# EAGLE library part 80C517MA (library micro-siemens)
MICROPROCESSOR/PERIPHERAL DEVICE

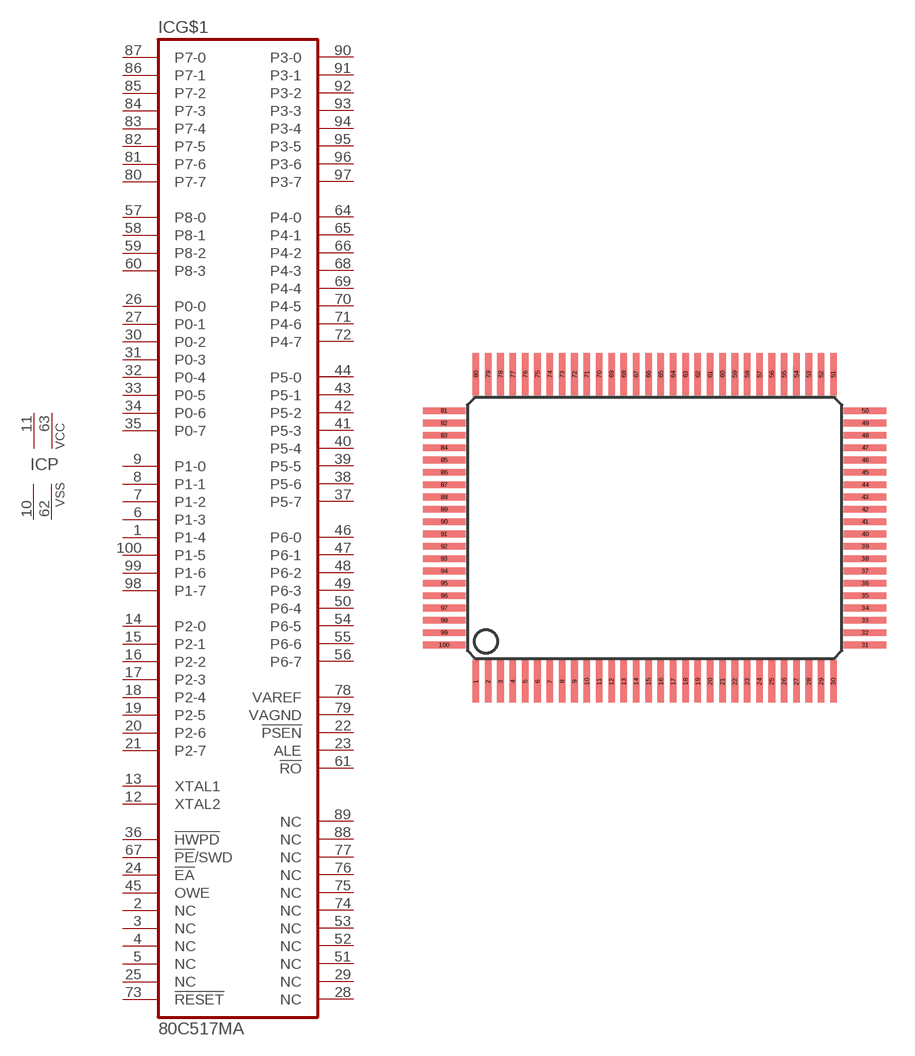
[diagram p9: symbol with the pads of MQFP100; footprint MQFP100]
Designator prefix IC; gates G$1=80C517MA P=2VCC2VSS

## 80C517MA (OC_FARNELL: unknown; OC_NEWARK: unknown)  [MQFP100]
1  G$1:P1-4
2  G$1:NC  nc
3  G$1:NC  nc
4  G$1:NC  nc
5  G$1:NC  nc
6  G$1:P1-3
7  G$1:P1-2
8  G$1:P1-1
9  G$1:P1-0
10  P:VSS  pwr
11  P:VCC  pwr
12  G$1:XTAL2  pas
13  G$1:XTAL1  pas
14  G$1:P2-0
15  G$1:P2-1
16  G$1:P2-2
17  G$1:P2-3
18  G$1:P2-4
19  G$1:P2-5
20  G$1:P2-6
21  G$1:P2-7
22  G$1:!PSEN  out
23  G$1:ALE  out
24  G$1:!EA  in
25  G$1:NC  nc
26  G$1:P0-0
27  G$1:P0-1
28  G$1:NC  nc
29  G$1:NC  nc
30  G$1:P0-2
31  G$1:P0-3
32  G$1:P0-4
33  G$1:P0-5
34  G$1:P0-6
35  G$1:P0-7
36  G$1:!HWPD  in
37  G$1:P5-7
38  G$1:P5-6
39  G$1:P5-5
40  G$1:P5-4
41  G$1:P5-3
42  G$1:P5-2
43  G$1:P5-1
44  G$1:P5-0
45  G$1:OWE  in
46  G$1:P6-0
47  G$1:P6-1
48  G$1:P6-2
49  G$1:P6-3
50  G$1:P6-4
51  G$1:NC  nc
52  G$1:NC  nc
53  G$1:NC  nc
54  G$1:P6-5
55  G$1:P6-6
56  G$1:P6-7
57  G$1:P8-0  in
58  G$1:P8-1  in
59  G$1:P8-2  in
60  G$1:P8-3  in
61  G$1:!RO  out
62  P:VSS  pwr
63  P:VCC  pwr
64  G$1:P4-0
65  G$1:P4-1
66  G$1:P4-2
67  G$1:!PE!/SWD  in
68  G$1:P4-3
69  G$1:P4-4
70  G$1:P4-5
71  G$1:P4-6
72  G$1:P4-7
73  G$1:!RESET  in
74  G$1:NC  nc
75  G$1:NC  nc
76  G$1:NC  nc
77  G$1:NC  nc
78  G$1:VAREF  pas
79  G$1:VAGND  pas
80  G$1:P7-7  in
81  G$1:P7-6  in
82  G$1:P7-5  in
83  G$1:P7-4  in
84  G$1:P7-3  in
85  G$1:P7-2  in
86  G$1:P7-1  in
87  G$1:P7-0  in
88  G$1:NC  nc
89  G$1:NC  nc
90  G$1:P3-0
91  G$1:P3-1
92  G$1:P3-2
93  G$1:P3-3
94  G$1:P3-4
95  G$1:P3-5
96  G$1:P3-6
97  G$1:P3-7
98  G$1:P1-7
99  G$1:P1-6
100  G$1:P1-5

## Footprint MQFP100 (pad centres in mm)
Metric Quad Flat Pack
smd 0.35 x 2.2: 1 -9.425,-8.1; 2 -8.775,-8.1; 3 -8.125,-8.1; 4 -7.475,-8.1; 5 -6.825,-8.1; 6 -6.175,-8.1; 7 -5.525,-8.1; 8 -4.875,-8.1; 9 -4.225,-8.1; 10 -3.575,-8.1; 11 -2.925,-8.1; 12 -2.275,-8.1; 13 -1.625,-8.1; 14 -0.975,-8.1; 15 -0.325,-8.1; 16 0.325,-8.1; 17 0.975,-8.1; 18 1.625,-8.1; 19 2.275,-8.1; 20 2.925,-8.1; 21 3.575,-8.1; 22 4.225,-8.1; 23 4.875,-8.1; 24 5.525,-8.1; 25 6.175,-8.1; 26 6.825,-8.1; 27 7.475,-8.1; 28 8.125,-8.1; 29 8.775,-8.1; 30 9.425,-8.1; 51 9.425,8.1; 52 8.775,8.1; 53 8.125,8.1; 54 7.475,8.1; 55 6.825,8.1; 56 6.175,8.1; 57 5.525,8.1; 58 4.875,8.1; 59 4.225,8.1; 60 3.575,8.1; 61 2.925,8.1; 62 2.275,8.1; 63 1.625,8.1; 64 0.975,8.1; 65 0.325,8.1; 66 -0.325,8.1; 67 -0.975,8.1; 68 -1.625,8.1; 69 -2.275,8.1; 70 -2.925,8.1; 71 -3.575,8.1; 72 -4.225,8.1; 73 -4.875,8.1; 74 -5.525,8.1; 75 -6.175,8.1; 76 -6.825,8.1; 77 -7.475,8.1; 78 -8.125,8.1; 79 -8.775,8.1; 80 -9.425,8.1
smd 2.2 x 0.35: 31 11.1,-6.175; 32 11.1,-5.525; 33 11.1,-4.875; 34 11.1,-4.225; 35 11.1,-3.575; 36 11.1,-2.925; 37 11.1,-2.275; 38 11.1,-1.625; 39 11.1,-0.975; 40 11.1,-0.325; 41 11.1,0.325; 42 11.1,0.975; 43 11.1,1.625; 44 11.1,2.275; 45 11.1,2.925; 46 11.1,3.575; 47 11.1,4.225; 48 11.1,4.875; 49 11.1,5.525; 50 11.1,6.175; 81 -11.1,6.175; 82 -11.1,5.525; 83 -11.1,4.875; 84 -11.1,4.225; 85 -11.1,3.575; 86 -11.1,2.925; 87 -11.1,2.275; 88 -11.1,1.625; 89 -11.1,0.975; 90 -11.1,0.325; 91 -11.1,-0.325; 92 -11.1,-0.975; 93 -11.1,-1.625; 94 -11.1,-2.275; 95 -11.1,-2.925; 96 -11.1,-3.575; 97 -11.1,-4.225; 98 -11.1,-4.875; 99 -11.1,-5.525; 100 -11.1,-6.175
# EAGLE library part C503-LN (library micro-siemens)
MICROPROCESSOR/PERIPHERAL DEVICE

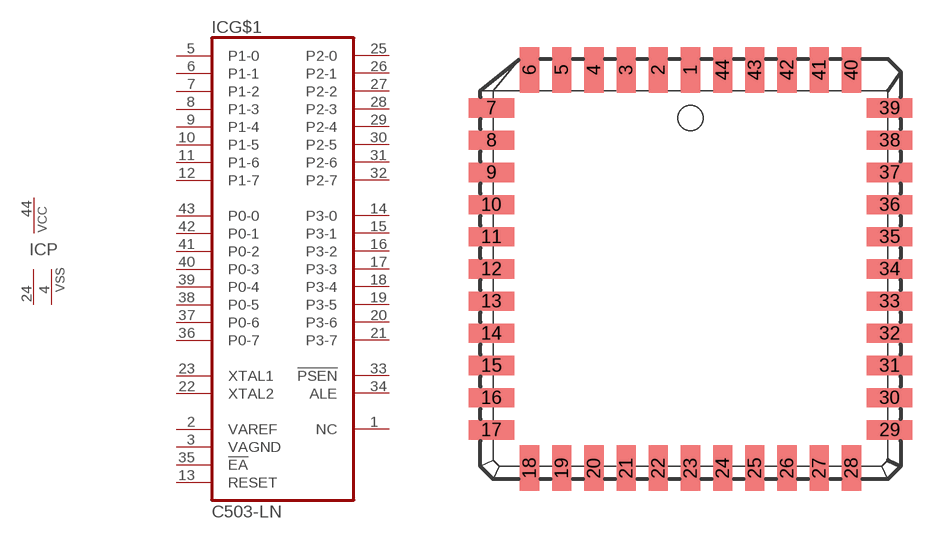
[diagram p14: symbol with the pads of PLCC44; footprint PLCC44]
Designator prefix IC; gates G$1=C503-LN P=1VCC2VSS

## C503-LN (OC_FARNELL: unknown; OC_NEWARK: unknown)  [PLCC44]
1  G$1:NC  nc
2  G$1:VAREF  pas
3  G$1:VAGND  pas
4  P:VSS  pwr
5  G$1:P1-0  in
6  G$1:P1-1  in
7  G$1:P1-2  in
8  G$1:P1-3  in
9  G$1:P1-4  in
10  G$1:P1-5  in
11  G$1:P1-6  in
12  G$1:P1-7  in
13  G$1:RESET  in
14  G$1:P3-0
15  G$1:P3-1
16  G$1:P3-2
17  G$1:P3-3
18  G$1:P3-4
19  G$1:P3-5
20  G$1:P3-6
21  G$1:P3-7
22  G$1:XTAL2  pas
23  G$1:XTAL1  pas
24  P:VSS  pwr
25  G$1:P2-0
26  G$1:P2-1
27  G$1:P2-2
28  G$1:P2-3
29  G$1:P2-4
30  G$1:P2-5
31  G$1:P2-6
32  G$1:P2-7
33  G$1:!PSEN  out
34  G$1:ALE  out
35  G$1:!EA  in
36  G$1:P0-7
37  G$1:P0-6
38  G$1:P0-5
39  G$1:P0-4
40  G$1:P0-3
41  G$1:P0-2
42  G$1:P0-1
43  G$1:P0-0
44  P:VCC  pwr

## Footprint PLCC44 (pad centres in mm)
PLASTIC LEADED CHIP CARRIER square
smd 0.76 x 1.8: 1 0,7.86; 2 -1.27,7.86; 3 -2.54,7.86; 4 -3.81,7.86; 5 -5.08,7.86; 6 -6.35,7.86; 18 -6.35,-7.86; 19 -5.08,-7.86; 20 -3.81,-7.86; 21 -2.54,-7.86; 22 -1.27,-7.86; 23 0,-7.86; 24 1.27,-7.86; 25 2.54,-7.86; 26 3.81,-7.86; 27 5.08,-7.86; 28 6.35,-7.86; 40 6.35,7.86; 41 5.08,7.86; 42 3.81,7.86; 43 2.54,7.86; 44 1.27,7.86
smd 1.8 x 0.76: 7 -7.86,6.35; 8 -7.86,5.08; 9 -7.86,3.81; 10 -7.86,2.54; 11 -7.86,1.27; 12 -7.86,0; 13 -7.86,-1.27; 14 -7.86,-2.54; 15 -7.86,-3.81; 16 -7.86,-5.08; 17 -7.86,-6.35; 29 7.86,-6.35; 30 7.86,-5.08; 31 7.86,-3.81; 32 7.86,-2.54; 33 7.86,-1.27; 34 7.86,0; 35 7.86,1.27; 36 7.86,2.54; 37 7.86,3.81; 38 7.86,5.08; 39 7.86,6.35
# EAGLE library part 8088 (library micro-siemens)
MICROPROCESSOR/PERIPHERAL DEVICE

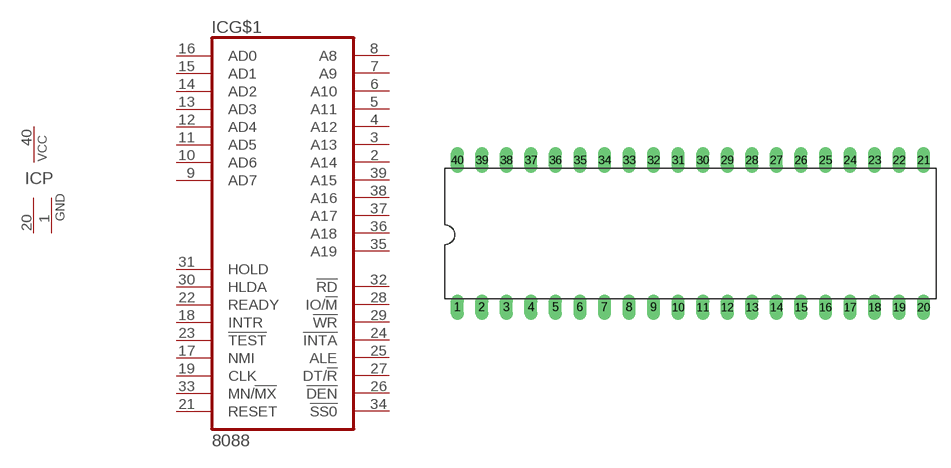
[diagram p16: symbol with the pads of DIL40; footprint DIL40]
Designator prefix IC; gates G$1=8088 P=1VCC2GND

## 8088 (OC_FARNELL: unknown; OC_NEWARK: unknown)  [DIL40]
1  P:GND  pwr
2  G$1:A14  out
3  G$1:A13  out
4  G$1:A12  out
5  G$1:A11  out
6  G$1:A10  out
7  G$1:A9  out
8  G$1:A8  out
9  G$1:AD7
10  G$1:AD6
11  G$1:AD5
12  G$1:AD4
13  G$1:AD3
14  G$1:AD2
15  G$1:AD1
16  G$1:AD0
17  G$1:NMI  in
18  G$1:INTR  in
19  G$1:CLK  in
20  P:GND  pwr
21  G$1:RESET  in
22  G$1:READY  in
23  G$1:!TEST  in
24  G$1:!INTA  in
25  G$1:ALE  in
26  G$1:!DEN  in
27  G$1:DT/!R  in
28  G$1:IO/!M  in
29  G$1:!WR  in
30  G$1:HLDA
31  G$1:HOLD
32  G$1:!RD  out
33  G$1:MN/!MX  in
34  G$1:!SS0  in
35  G$1:A19  out
36  G$1:A18  out
37  G$1:A17  out
38  G$1:A16  out
39  G$1:A15  out
40  P:VCC  pwr

## Footprint DIL40 (pad centres in mm)
Dual In Line Package
drill 0.813 long: 1 -24.13,-7.62; 2 -21.59,-7.62; 3 -19.05,-7.62; 4 -16.51,-7.62; 5 -13.97,-7.62; 6 -11.43,-7.62; 7 -8.89,-7.62; 8 -6.35,-7.62; 9 -3.81,-7.62; 10 -1.27,-7.62; 11 1.27,-7.62; 12 3.81,-7.62; 13 6.35,-7.62; 14 8.89,-7.62; 15 11.43,-7.62; 16 13.97,-7.62; 17 16.51,-7.62; 18 19.05,-7.62; 19 21.59,-7.62; 20 24.13,-7.62; 21 24.13,7.62; 22 21.59,7.62; 23 19.05,7.62; 24 16.51,7.62; 25 13.97,7.62; 26 11.43,7.62; 27 8.89,7.62; 28 6.35,7.62; 29 3.81,7.62; 30 1.27,7.62; 31 -1.27,7.62; 32 -3.81,7.62; 33 -6.35,7.62; 34 -8.89,7.62; 35 -11.43,7.62; 36 -13.97,7.62; 37 -16.51,7.62; 38 -19.05,7.62; 39 -21.59,7.62; 40 -24.13,7.62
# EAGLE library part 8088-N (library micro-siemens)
MICROPROCESSOR/PERIPHERAL DEVICE

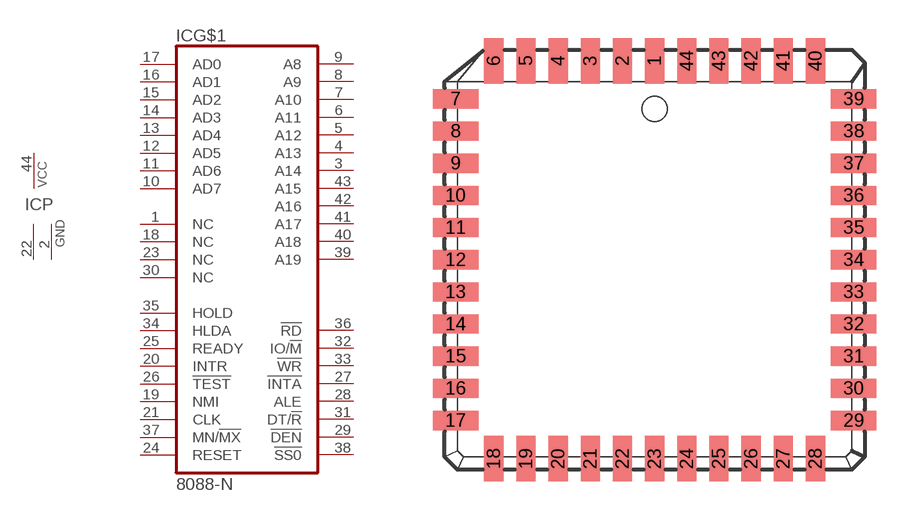
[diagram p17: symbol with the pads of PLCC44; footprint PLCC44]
Designator prefix IC; gates G$1=8088-N P=1VCC2GND

## 8088-N (OC_FARNELL: unknown; OC_NEWARK: unknown)  [PLCC44]
1  G$1:NC  nc
2  P:GND  pwr
3  G$1:A14  out
4  G$1:A13  out
5  G$1:A12  out
6  G$1:A11  out
7  G$1:A10  out
8  G$1:A9  out
9  G$1:A8  out
10  G$1:AD7
11  G$1:AD6
12  G$1:AD5
13  G$1:AD4
14  G$1:AD3
15  G$1:AD2
16  G$1:AD1
17  G$1:AD0
18  G$1:NC  nc
19  G$1:NMI  in
20  G$1:INTR  in
21  G$1:CLK  in
22  P:GND  pwr
23  G$1:NC  nc
24  G$1:RESET  in
25  G$1:READY  in
26  G$1:!TEST  in
27  G$1:!INTA  in
28  G$1:ALE  in
29  G$1:!DEN  in
30  G$1:NC  nc
31  G$1:DT/!R  in
32  G$1:IO/!M  in
33  G$1:!WR  in
34  G$1:HLDA
35  G$1:HOLD
36  G$1:!RD  out
37  G$1:MN/!MX  in
38  G$1:!SS0  in
39  G$1:A19  nc
40  G$1:A18  out
41  G$1:A17  out
42  G$1:A16  out
43  G$1:A15  out
44  P:VCC  pwr

## Footprint PLCC44 (pad centres in mm)
PLASTIC LEADED CHIP CARRIER square
smd 0.76 x 1.8: 1 0,7.86; 2 -1.27,7.86; 3 -2.54,7.86; 4 -3.81,7.86; 5 -5.08,7.86; 6 -6.35,7.86; 18 -6.35,-7.86; 19 -5.08,-7.86; 20 -3.81,-7.86; 21 -2.54,-7.86; 22 -1.27,-7.86; 23 0,-7.86; 24 1.27,-7.86; 25 2.54,-7.86; 26 3.81,-7.86; 27 5.08,-7.86; 28 6.35,-7.86; 40 6.35,7.86; 41 5.08,7.86; 42 3.81,7.86; 43 2.54,7.86; 44 1.27,7.86
smd 1.8 x 0.76: 7 -7.86,6.35; 8 -7.86,5.08; 9 -7.86,3.81; 10 -7.86,2.54; 11 -7.86,1.27; 12 -7.86,0; 13 -7.86,-1.27; 14 -7.86,-2.54; 15 -7.86,-3.81; 16 -7.86,-5.08; 17 -7.86,-6.35; 29 7.86,-6.35; 30 7.86,-5.08; 31 7.86,-3.81; 32 7.86,-2.54; 33 7.86,-1.27; 34 7.86,0; 35 7.86,1.27; 36 7.86,2.54; 37 7.86,3.81; 38 7.86,5.08; 39 7.86,6.35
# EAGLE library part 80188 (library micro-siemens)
MICROPROCESSOR/PERIPHERAL DEVICE

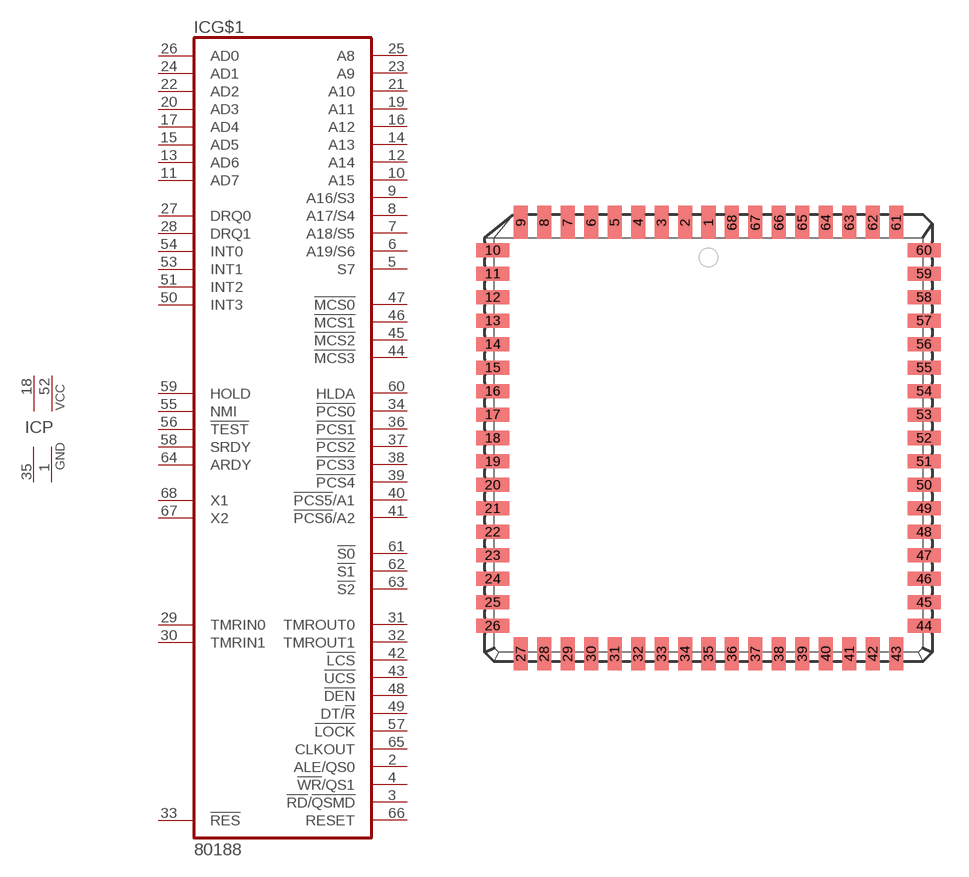
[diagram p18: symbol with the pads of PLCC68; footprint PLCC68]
Designator prefix IC; gates G$1=80188 P=2VCC2GND

## 80188 (OC_FARNELL: unknown; OC_NEWARK: unknown)  [PLCC68]
1  P:GND  pwr
2  G$1:ALE/QS0  out
3  G$1:!RD!/!QSMD  out
4  G$1:!WR!/QS1  out
5  G$1:S7  out
6  G$1:A19/S6  out
7  G$1:A18/S5  out
8  G$1:A17/S4  out
9  G$1:A16/S3  out
10  G$1:A15  out
11  G$1:AD7
12  G$1:A14  out
13  G$1:AD6
14  G$1:A13  out
15  G$1:AD5
16  G$1:A12  out
17  G$1:AD4
18  P:VCC  pwr
19  G$1:A11  out
20  G$1:AD3
21  G$1:A10  out
22  G$1:AD2
23  G$1:A9  out
24  G$1:AD1
25  G$1:A8  out
26  G$1:AD0
27  G$1:DRQ0  in
28  G$1:DRQ1  in
29  G$1:TMRIN0  in
30  G$1:TMRIN1  in
31  G$1:TMROUT0  out
32  G$1:TMROUT1  out
33  G$1:!RES  in
34  G$1:!PCS0  out
35  P:GND  pwr
36  G$1:!PCS1  out
37  G$1:!PCS2  out
38  G$1:!PCS3  out
39  G$1:!PCS4  out
40  G$1:!PCS5!/A1  out
41  G$1:!PCS6!/A2  out
42  G$1:!LCS  out
43  G$1:!UCS  out
44  G$1:!MCS3  out
45  G$1:!MCS2  out
46  G$1:!MCS1  out
47  G$1:!MCS0  out
48  G$1:!DEN  out
49  G$1:DT/!R  out
50  G$1:INT3
51  G$1:INT2
52  P:VCC  pwr
53  G$1:INT1  in
54  G$1:INT0  in
55  G$1:NMI  in
56  G$1:!TEST  in
57  G$1:!LOCK  out
58  G$1:SRDY  out
59  G$1:HOLD  in
60  G$1:HLDA  out
61  G$1:!S0  out
62  G$1:!S1  out
63  G$1:!S2  out
64  G$1:ARDY  out
65  G$1:CLKOUT  out
66  G$1:RESET  out
67  G$1:X2  out
68  G$1:X1  out

## Footprint PLCC68 (pad centres in mm)
PLASTIC LEADED CHIP CARRIER square
smd 0.76 x 1.8: 1 0,11.67; 2 -1.27,11.67; 3 -2.54,11.67; 4 -3.81,11.67; 5 -5.08,11.67; 6 -6.35,11.67; 7 -7.62,11.67; 8 -8.89,11.67; 9 -10.16,11.67; 27 -10.16,-11.67; 28 -8.89,-11.67; 29 -7.62,-11.67; 30 -6.35,-11.67; 31 -5.08,-11.67; 32 -3.81,-11.67; 33 -2.54,-11.67; 34 -1.27,-11.67; 35 0,-11.67; 36 1.27,-11.67; 37 2.54,-11.67; 38 3.81,-11.67; 39 5.08,-11.67; 40 6.35,-11.67; 41 7.62,-11.67; 42 8.89,-11.67; 43 10.16,-11.67; 61 10.16,11.67; 62 8.89,11.67; 63 7.62,11.67; 64 6.35,11.67; 65 5.08,11.67; 66 3.81,11.67; 67 2.54,11.67; 68 1.27,11.67
smd 1.8 x 0.76: 10 -11.67,10.16; 11 -11.67,8.89; 12 -11.67,7.62; 13 -11.67,6.35; 14 -11.67,5.08; 15 -11.67,3.81; 16 -11.67,2.54; 17 -11.67,1.27; 18 -11.67,0; 19 -11.67,-1.27; 20 -11.67,-2.54; 21 -11.67,-3.81; 22 -11.67,-5.08; 23 -11.67,-6.35; 24 -11.67,-7.62; 25 -11.67,-8.89; 26 -11.67,-10.16; 44 11.67,-10.16; 45 11.67,-8.89; 46 11.67,-7.62; 47 11.67,-6.35; 48 11.67,-5.08; 49 11.67,-3.81; 50 11.67,-2.54; 51 11.67,-1.27; 52 11.67,0; 53 11.67,1.27; 54 11.67,2.54; 55 11.67,3.81; 56 11.67,5.08; 57 11.67,6.35; 58 11.67,7.62; 59 11.67,8.89; 60 11.67,10.16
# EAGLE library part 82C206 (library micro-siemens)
MICROPROCESSOR/PERIPHERAL DEVICE

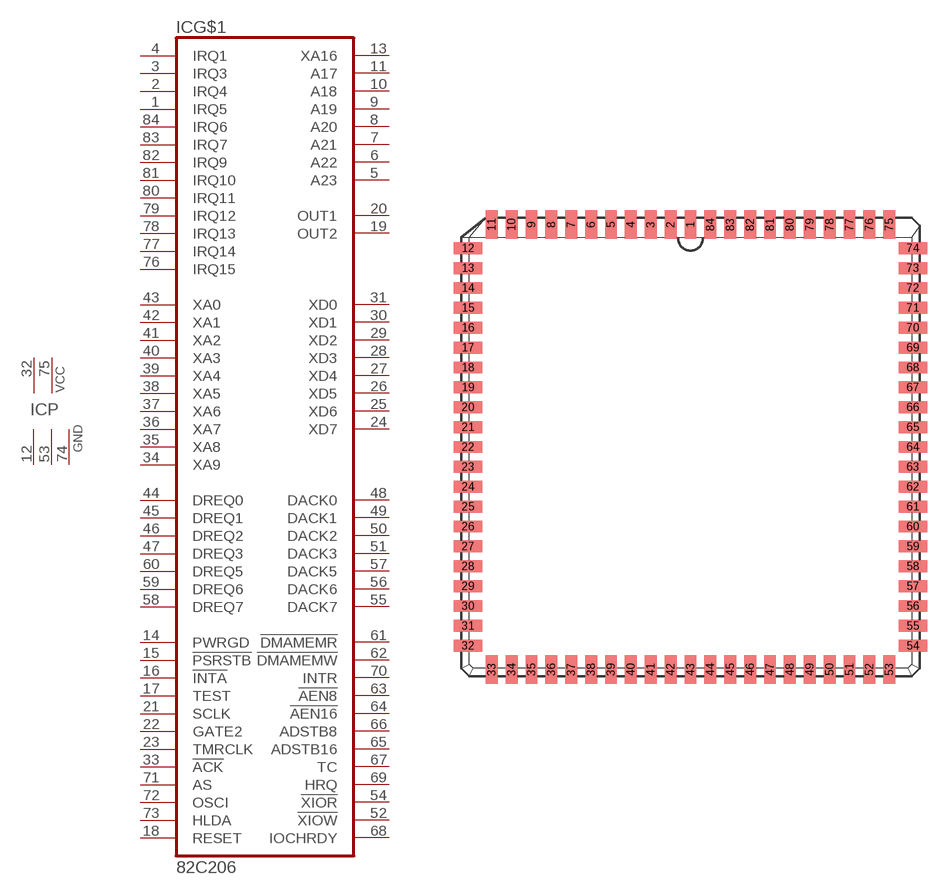
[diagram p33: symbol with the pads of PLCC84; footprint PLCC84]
Designator prefix IC; gates G$1=82C206 P=2VCC3GND

## 82C206 (OC_FARNELL: unknown; OC_NEWARK: unknown)  [PLCC84]
1  G$1:IRQ5  in
2  G$1:IRQ4  in
3  G$1:IRQ3  in
4  G$1:IRQ1  in
5  G$1:A23  out
6  G$1:A22  out
7  G$1:A21  out
8  G$1:A20  out
9  G$1:A19  out
10  G$1:A18  out
11  G$1:A17  out
12  P:GND  pwr
13  G$1:XA16  out
14  G$1:PWRGD  in
15  G$1:!PSRSTB  in
16  G$1:!INTA  in
17  G$1:TEST  in
18  G$1:RESET  in
19  G$1:OUT2  out
20  G$1:OUT1  out
21  G$1:SCLK  in
22  G$1:GATE2  in
23  G$1:TMRCLK  in
24  G$1:XD7
25  G$1:XD6
26  G$1:XD5
27  G$1:XD4
28  G$1:XD3
29  G$1:XD2
30  G$1:XD1
31  G$1:XD0
32  P:VCC  pwr
33  G$1:!ACK  in
34  G$1:XA9  in
35  G$1:XA8
36  G$1:XA7
37  G$1:XA6
38  G$1:XA5
39  G$1:XA4
40  G$1:XA3
41  G$1:XA2
42  G$1:XA1
43  G$1:XA0
44  G$1:DREQ0  in
45  G$1:DREQ1  in
46  G$1:DREQ2  in
47  G$1:DREQ3  in
48  G$1:DACK0  out
49  G$1:DACK1  out
50  G$1:DACK2  out
51  G$1:DACK3  out
52  G$1:!XIOW
53  P:GND  pwr
54  G$1:!XIOR
55  G$1:DACK7  out
56  G$1:DACK6  out
57  G$1:DACK5  out
58  G$1:DREQ7  in
59  G$1:DREQ6  in
60  G$1:DREQ5  in
61  G$1:!DMAMEMR  out
62  G$1:!DMAMEMW  out
63  G$1:!AEN8  out
64  G$1:!AEN16  out
65  G$1:ADSTB16  out
66  G$1:ADSTB8  out
67  G$1:TC  out
68  G$1:IOCHRDY
69  G$1:HRQ  out
70  G$1:INTR  out
71  G$1:AS  in
72  G$1:OSCI  in
73  G$1:HLDA  in
74  P:GND  pwr
75  P:VCC  pwr
76  G$1:IRQ15  in
77  G$1:IRQ14  in
78  G$1:IRQ13  in
79  G$1:IRQ12  in
80  G$1:IRQ11  in
81  G$1:IRQ10  in
82  G$1:IRQ9  in
83  G$1:IRQ7  in
84  G$1:IRQ6  in

## Footprint PLCC84 (pad centres in mm)
PLASTIC LEADED CHIP CARRIER square
smd 0.76 x 1.8: 1 0,14.21; 2 -1.27,14.21; 3 -2.54,14.21; 4 -3.81,14.21; 5 -5.08,14.21; 6 -6.35,14.21; 7 -7.62,14.21; 8 -8.89,14.21; 9 -10.16,14.21; 10 -11.43,14.21; 11 -12.7,14.21; 33 -12.7,-14.21; 34 -11.43,-14.21; 35 -10.16,-14.21; 36 -8.89,-14.21; 37 -7.62,-14.21; 38 -6.35,-14.21; 39 -5.08,-14.21; 40 -3.81,-14.21; 41 -2.54,-14.21; 42 -1.27,-14.21; 43 0,-14.21; 44 1.27,-14.21; 45 2.54,-14.21; 46 3.81,-14.21; 47 5.08,-14.21; 48 6.35,-14.21; 49 7.62,-14.21; 50 8.89,-14.21; 51 10.16,-14.21; 52 11.43,-14.21; 53 12.7,-14.21; 75 12.7,14.21; 76 11.43,14.21; 77 10.16,14.21; 78 8.89,14.21; 79 7.62,14.21; 80 6.35,14.21; 81 5.08,14.21; 82 3.81,14.21; 83 2.54,14.21; 84 1.27,14.21
smd 1.8 x 0.76: 12 -14.21,12.7; 13 -14.21,11.43; 14 -14.21,10.16; 15 -14.21,8.89; 16 -14.21,7.62; 17 -14.21,6.35; 18 -14.21,5.08; 19 -14.21,3.81; 20 -14.21,2.54; 21 -14.21,1.27; 22 -14.21,0; 23 -14.21,-1.27; 24 -14.21,-2.54; 25 -14.21,-3.81; 26 -14.21,-5.08; 27 -14.21,-6.35; 28 -14.21,-7.62; 29 -14.21,-8.89; 30 -14.21,-10.16; 31 -14.21,-11.43; 32 -14.21,-12.7; 54 14.21,-12.7; 55 14.21,-11.43; 56 14.21,-10.16; 57 14.21,-8.89; 58 14.21,-7.62; 59 14.21,-6.35; 60 14.21,-5.08; 61 14.21,-3.81; 62 14.21,-2.54; 63 14.21,-1.27; 64 14.21,0; 65 14.21,1.27; 66 14.21,2.54; 67 14.21,3.81; 68 14.21,5.08; 69 14.21,6.35; 70 14.21,7.62; 71 14.21,8.89; 72 14.21,10.16; 73 14.21,11.43; 74 14.21,12.7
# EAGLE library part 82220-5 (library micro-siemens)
MICROPROCESSOR/PERIPHERAL DEVICE

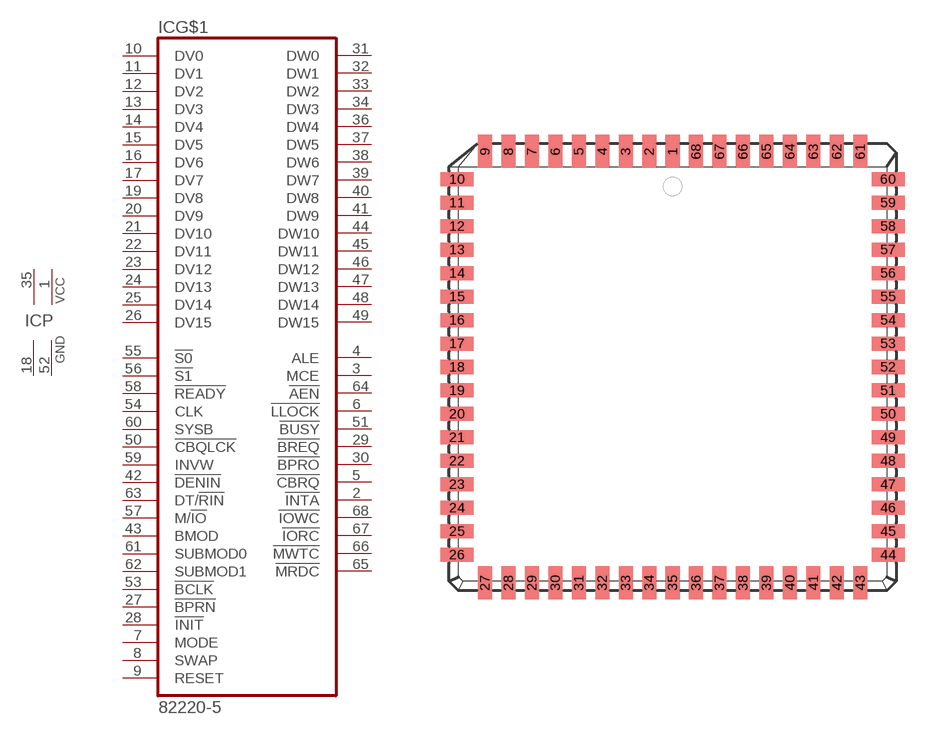
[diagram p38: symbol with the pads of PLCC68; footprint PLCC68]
Designator prefix IC; gates G$1=82220-5 P=2VCC2GND

## 82220-5 (OC_FARNELL: unknown; OC_NEWARK: unknown)  [PLCC68]
1  P:VCC  pwr
2  G$1:!INTA  out
3  G$1:MCE  out
4  G$1:ALE  out
5  G$1:!CBRQ
6  G$1:!LLOCK  out
7  G$1:MODE  in
8  G$1:SWAP  in
9  G$1:RESET  in
10  G$1:DV0
11  G$1:DV1
12  G$1:DV2
13  G$1:DV3
14  G$1:DV4
15  G$1:DV5
16  G$1:DV6
17  G$1:DV7
18  P:GND  pwr
19  G$1:DV8
20  G$1:DV9
21  G$1:DV10
22  G$1:DV11
23  G$1:DV12
24  G$1:DV13
25  G$1:DV14
26  G$1:DV15
27  G$1:!BPRN  in
28  G$1:!INIT  in
29  G$1:!BREQ  out
30  G$1:!BPRO  out
31  G$1:DW0
32  G$1:DW1
33  G$1:DW2
34  G$1:DW3
35  P:VCC  pwr
36  G$1:DW4
37  G$1:DW5
38  G$1:DW6
39  G$1:DW7
40  G$1:DW8
41  G$1:DW9
42  G$1:!DENIN  in
43  G$1:BMOD  in
44  G$1:DW10
45  G$1:DW11
46  G$1:DW12
47  G$1:DW13
48  G$1:DW14
49  G$1:DW15
50  G$1:!CBQLCK  in
51  G$1:!BUSY
52  P:GND  pwr
53  G$1:!BCLK  in
54  G$1:CLK  in
55  G$1:!S0  in
56  G$1:!S1  in
57  G$1:M/!IO  in
58  G$1:!READY  in
59  G$1:INVW  in
60  G$1:SYSB  in
61  G$1:SUBMOD0  in
62  G$1:SUBMOD1  in
63  G$1:DT/!RIN  in
64  G$1:!AEN  out
65  G$1:!MRDC  out
66  G$1:!MWTC  out
67  G$1:!IORC  out
68  G$1:!IOWC  out

## Footprint PLCC68 (pad centres in mm)
PLASTIC LEADED CHIP CARRIER square
smd 0.76 x 1.8: 1 0,11.67; 2 -1.27,11.67; 3 -2.54,11.67; 4 -3.81,11.67; 5 -5.08,11.67; 6 -6.35,11.67; 7 -7.62,11.67; 8 -8.89,11.67; 9 -10.16,11.67; 27 -10.16,-11.67; 28 -8.89,-11.67; 29 -7.62,-11.67; 30 -6.35,-11.67; 31 -5.08,-11.67; 32 -3.81,-11.67; 33 -2.54,-11.67; 34 -1.27,-11.67; 35 0,-11.67; 36 1.27,-11.67; 37 2.54,-11.67; 38 3.81,-11.67; 39 5.08,-11.67; 40 6.35,-11.67; 41 7.62,-11.67; 42 8.89,-11.67; 43 10.16,-11.67; 61 10.16,11.67; 62 8.89,11.67; 63 7.62,11.67; 64 6.35,11.67; 65 5.08,11.67; 66 3.81,11.67; 67 2.54,11.67; 68 1.27,11.67
smd 1.8 x 0.76: 10 -11.67,10.16; 11 -11.67,8.89; 12 -11.67,7.62; 13 -11.67,6.35; 14 -11.67,5.08; 15 -11.67,3.81; 16 -11.67,2.54; 17 -11.67,1.27; 18 -11.67,0; 19 -11.67,-1.27; 20 -11.67,-2.54; 21 -11.67,-3.81; 22 -11.67,-5.08; 23 -11.67,-6.35; 24 -11.67,-7.62; 25 -11.67,-8.89; 26 -11.67,-10.16; 44 11.67,-10.16; 45 11.67,-8.89; 46 11.67,-7.62; 47 11.67,-6.35; 48 11.67,-5.08; 49 11.67,-3.81; 50 11.67,-2.54; 51 11.67,-1.27; 52 11.67,0; 53 11.67,1.27; 54 11.67,2.54; 55 11.67,3.81; 56 11.67,5.08; 57 11.67,6.35; 58 11.67,7.62; 59 11.67,8.89; 60 11.67,10.16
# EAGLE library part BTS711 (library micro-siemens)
MICROPROCESSOR/PERIPHERAL DEVICE

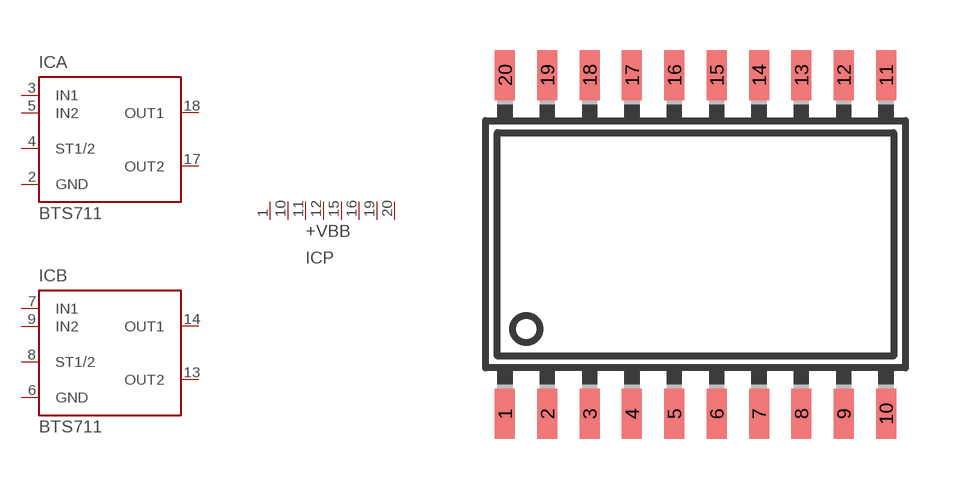
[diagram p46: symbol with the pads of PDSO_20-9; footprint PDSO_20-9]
Designator prefix IC; gates A=BTS711 B=BTS711 P=+VBB

## BTS711 (MF: FARNELL; MPN: BTS711L1.; OC_FARNELL: 743380; OC_NEWARK: 46WX1412)  [PDSO_20-9]
1  P:+VBB  pwr
2  A:GND  pwr
3  A:IN1  in
4  A:ST1/2  oc
5  A:IN2  in
6  B:GND  pwr
7  B:IN1  in
8  B:ST1/2  oc
9  B:IN2  in
10  P:+VBB  pwr
11  P:+VBB  pwr
12  P:+VBB  pwr
13  B:OUT2  out
14  B:OUT1  out
15  P:+VBB  pwr
16  P:+VBB  pwr
17  A:OUT2  out
18  A:OUT1  out
19  P:+VBB  pwr
20  P:+VBB  pwr

## Footprint PDSO_20-9 (pad centres in mm)
Plastic Small Outline
smd 0.6 x 1.5: 1 -5.715,-5.08; 2 -4.445,-5.08; 3 -3.175,-5.08; 4 -1.905,-5.08; 5 -0.635,-5.08; 6 0.635,-5.08; 7 1.905,-5.08; 8 3.175,-5.08; 9 4.445,-5.08; 10 5.715,-5.08; 11 5.715,5.08; 12 4.445,5.08; 13 3.175,5.08; 14 1.905,5.08; 15 0.635,5.08; 16 -0.635,5.08; 17 -1.905,5.08; 18 -3.175,5.08; 19 -4.445,5.08; 20 -5.715,5.08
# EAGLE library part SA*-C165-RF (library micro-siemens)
16 bit MICROPROCESSOR

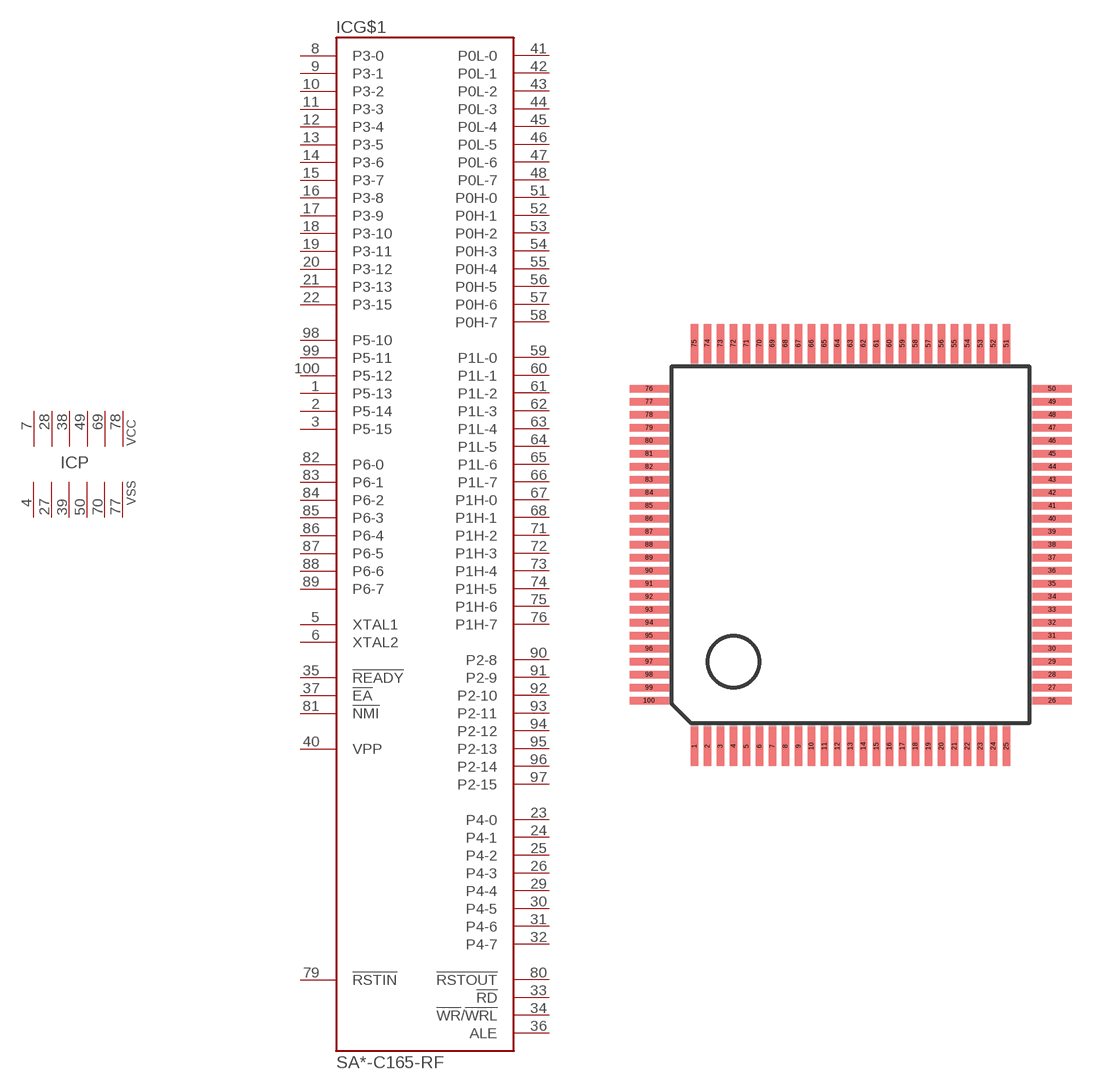
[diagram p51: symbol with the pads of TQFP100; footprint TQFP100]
Designator prefix IC; gates G$1=C165-1 P=6_VCCVSS

## SAB-C165-RF (OC_FARNELL: unknown; OC_NEWARK: unknown), SAK-C165-RF (OC_FARNELL: unknown; OC_NEWARK: unknown)  [TQFP100]
1  G$1:P5-13  in
2  G$1:P5-14  in
3  G$1:P5-15  in
4  P:VSS  pwr
5  G$1:XTAL1  in
6  G$1:XTAL2  out
7  P:VCC  pwr
8  G$1:P3-0
9  G$1:P3-1
10  G$1:P3-2
11  G$1:P3-3
12  G$1:P3-4
13  G$1:P3-5
14  G$1:P3-6
15  G$1:P3-7
16  G$1:P3-8
17  G$1:P3-9
18  G$1:P3-10
19  G$1:P3-11
20  G$1:P3-12
21  G$1:P3-13
22  G$1:P3-15
23  G$1:P4-0
24  G$1:P4-1
25  G$1:P4-2
26  G$1:P4-3
27  P:VSS  pwr
28  P:VCC  pwr
29  G$1:P4-4
30  G$1:P4-5
31  G$1:P4-6
32  G$1:P4-7
33  G$1:!RD  out
34  G$1:!WR!/!WRL  out
35  G$1:!READY  in
36  G$1:ALE  out
37  G$1:!EA  in
38  P:VCC  pwr
39  P:VSS  pwr
40  G$1:VPP  pas
41  G$1:P0L-0
42  G$1:P0L-1
43  G$1:P0L-2
44  G$1:P0L-3
45  G$1:P0L-4
46  G$1:P0L-5
47  G$1:P0L-6
48  G$1:P0L-7
49  P:VCC  pwr
50  P:VSS  pwr
51  G$1:P0H-0
52  G$1:P0H-1
53  G$1:P0H-2
54  G$1:P0H-3
55  G$1:P0H-4
56  G$1:P0H-5
57  G$1:P0H-6
58  G$1:P0H-7
59  G$1:P1L-0
60  G$1:P1L-1
61  G$1:P1L-2
62  G$1:P1L-3
63  G$1:P1L-4
64  G$1:P1L-5
65  G$1:P1L-6
66  G$1:P1L-7
67  G$1:P1H-0
68  G$1:P1H-1
69  P:VCC  pwr
70  P:VSS  pwr
71  G$1:P1H-2
72  G$1:P1H-3
73  G$1:P1H-4
74  G$1:P1H-5
75  G$1:P1H-6
76  G$1:P1H-7
77  P:VSS  pwr
78  P:VCC  pwr
79  G$1:!RSTIN  in
80  G$1:!RSTOUT  out
81  G$1:!NMI  in
82  G$1:P6-0
83  G$1:P6-1
84  G$1:P6-2
85  G$1:P6-3
86  G$1:P6-4
87  G$1:P6-5
88  G$1:P6-6
89  G$1:P6-7
90  G$1:P2-8
91  G$1:P2-9
92  G$1:P2-10
93  G$1:P2-11
94  G$1:P2-12
95  G$1:P2-13
96  G$1:P2-14
97  G$1:P2-15
98  G$1:P5-10  in
99  G$1:P5-11  in
100  G$1:P5-12  in

## Footprint TQFP100 (pad centres in mm)
Thin Quad Flat Pack
smd 0.27 x 1.5: 1 -6,-7.75; 2 -5.5,-7.75; 3 -5,-7.75; 4 -4.5,-7.75; 5 -4,-7.75; 6 -3.5,-7.75; 7 -3,-7.75; 8 -2.5,-7.75; 9 -2,-7.75; 10 -1.5,-7.75; 11 -1,-7.75; 12 -0.5,-7.75; 13 0,-7.75; 14 0.5,-7.75; 15 1,-7.75; 16 1.5,-7.75; 17 2,-7.75; 18 2.5,-7.75; 19 3,-7.75; 20 3.5,-7.75; 21 4,-7.75; 22 4.5,-7.75; 23 5,-7.75; 24 5.5,-7.75; 25 6,-7.75; 51 6,7.75; 52 5.5,7.75; 53 5,7.75; 54 4.5,7.75; 55 4,7.75; 56 3.5,7.75; 57 3,7.75; 58 2.5,7.75; 59 2,7.75; 60 1.5,7.75; 61 1,7.75; 62 0.5,7.75; 63 0,7.75; 64 -0.5,7.75; 65 -1,7.75; 66 -1.5,7.75; 67 -2,7.75; 68 -2.5,7.75; 69 -3,7.75; 70 -3.5,7.75; 71 -4,7.75; 72 -4.5,7.75; 73 -5,7.75; 74 -5.5,7.75; 75 -6,7.75
smd 1.5 x 0.27: 26 7.75,-6; 27 7.75,-5.5; 28 7.75,-5; 29 7.75,-4.5; 30 7.75,-4; 31 7.75,-3.5; 32 7.75,-3; 33 7.75,-2.5; 34 7.75,-2; 35 7.75,-1.5; 36 7.75,-1; 37 7.75,-0.5; 38 7.75,0; 39 7.75,0.5; 40 7.75,1; 41 7.75,1.5; 42 7.75,2; 43 7.75,2.5; 44 7.75,3; 45 7.75,3.5; 46 7.75,4; 47 7.75,4.5; 48 7.75,5; 49 7.75,5.5; 50 7.75,6; 76 -7.75,6; 77 -7.75,5.5; 78 -7.75,5; 79 -7.75,4.5; 80 -7.75,4; 81 -7.75,3.5; 82 -7.75,3; 83 -7.75,2.5; 84 -7.75,2; 85 -7.75,1.5; 86 -7.75,1; 87 -7.75,0.5; 88 -7.75,0; 89 -7.75,-0.5; 90 -7.75,-1; 91 -7.75,-1.5; 92 -7.75,-2; 93 -7.75,-2.5; 94 -7.75,-3; 95 -7.75,-3.5; 96 -7.75,-4; 97 -7.75,-4.5; 98 -7.75,-5; 99 -7.75,-5.5; 100 -7.75,-6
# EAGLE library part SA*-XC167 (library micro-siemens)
16-Bit Single-Chip Microcontroller Source: xc167_ds_v1.1_2003_06.pdf

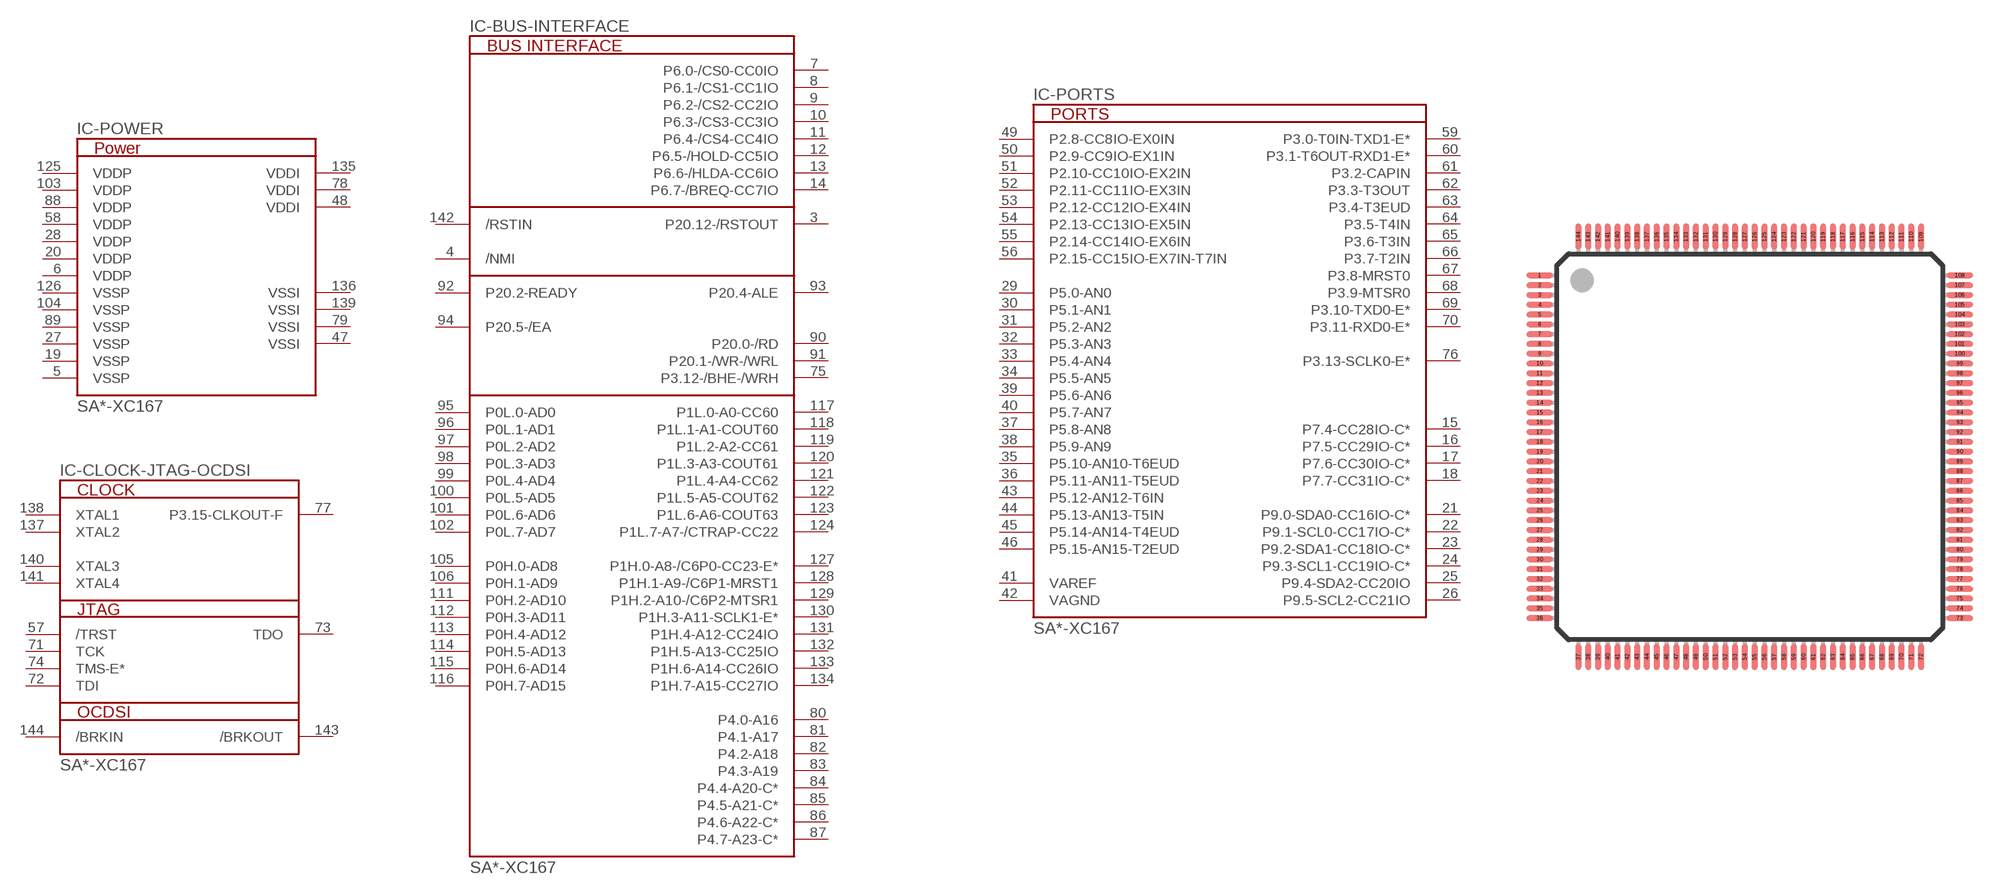
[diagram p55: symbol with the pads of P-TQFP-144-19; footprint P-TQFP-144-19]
Designator prefix IC; gates -POWER=XC167-POWER -BUS-INTERFACE=XC167-BUS -CLOCK-JTAG-OCDSI=XC167-CLOCK-JTAG -PORTS=XC167-PORTS

## SAB-XC167P (OC_FARNELL: unknown; OC_NEWARK: unknown), SAF-XC167P (OC_FARNELL: unknown; OC_NEWARK: unknown), SAK-XC167P (OC_FARNELL: unknown; OC_NEWARK: unknown)  [P-TQFP-144-19]
3  -BUS-INTERFACE:P20.12-/RSTOUT
4  -BUS-INTERFACE:/NMI  in
5  -POWER:VSSP  pwr
6  -POWER:VDDP  pwr
7  -BUS-INTERFACE:P6.0-/CS0-CC0IO
8  -BUS-INTERFACE:P6.1-/CS1-CC1IO
9  -BUS-INTERFACE:P6.2-/CS2-CC2IO
10  -BUS-INTERFACE:P6.3-/CS3-CC3IO
11  -BUS-INTERFACE:P6.4-/CS4-CC4IO
12  -BUS-INTERFACE:P6.5-/HOLD-CC5IO
13  -BUS-INTERFACE:P6.6-/HLDA-CC6IO
14  -BUS-INTERFACE:P6.7-/BREQ-CC7IO
15  -PORTS:P7.4-CC28IO-C*
16  -PORTS:P7.5-CC29IO-C*
17  -PORTS:P7.6-CC30IO-C*
18  -PORTS:P7.7-CC31IO-C*
19  -POWER:VSSP  pwr
20  -POWER:VDDP  pwr
21  -PORTS:P9.0-SDA0-CC16IO-C*
22  -PORTS:P9.1-SCL0-CC17IO-C*
23  -PORTS:P9.2-SDA1-CC18IO-C*
24  -PORTS:P9.3-SCL1-CC19IO-C*
25  -PORTS:P9.4-SDA2-CC20IO
26  -PORTS:P9.5-SCL2-CC21IO
27  -POWER:VSSP  pwr
28  -POWER:VDDP  pwr
29  -PORTS:P5.0-AN0  in
30  -PORTS:P5.1-AN1  in
31  -PORTS:P5.2-AN2  in
32  -PORTS:P5.3-AN3  in
33  -PORTS:P5.4-AN4  in
34  -PORTS:P5.5-AN5  in
35  -PORTS:P5.10-AN10-T6EUD  in
36  -PORTS:P5.11-AN11-T5EUD  in
37  -PORTS:P5.8-AN8  in
38  -PORTS:P5.9-AN9  in
39  -PORTS:P5.6-AN6  in
40  -PORTS:P5.7-AN7  in
41  -PORTS:VAREF  pas
42  -PORTS:VAGND  pas
43  -PORTS:P5.12-AN12-T6IN  in
44  -PORTS:P5.13-AN13-T5IN  in
45  -PORTS:P5.14-AN14-T4EUD  in
46  -PORTS:P5.15-AN15-T2EUD  in
47  -POWER:VSSI  out
48  -POWER:VDDI  pwr
49  -PORTS:P2.8-CC8IO-EX0IN
50  -PORTS:P2.9-CC9IO-EX1IN
51  -PORTS:P2.10-CC10IO-EX2IN
52  -PORTS:P2.11-CC11IO-EX3IN
53  -PORTS:P2.12-CC12IO-EX4IN
54  -PORTS:P2.13-CC13IO-EX5IN
55  -PORTS:P2.14-CC14IO-EX6IN
56  -PORTS:P2.15-CC15IO-EX7IN-T7IN
57  -CLOCK-JTAG-OCDSI:/TRST  in
58  -POWER:VDDP  pwr
59  -PORTS:P3.0-T0IN-TXD1-E*
60  -PORTS:P3.1-T6OUT-RXD1-E*
61  -PORTS:P3.2-CAPIN
62  -PORTS:P3.3-T3OUT
63  -PORTS:P3.4-T3EUD
64  -PORTS:P3.5-T4IN
65  -PORTS:P3.6-T3IN
66  -PORTS:P3.7-T2IN
67  -PORTS:P3.8-MRST0
68  -PORTS:P3.9-MTSR0
69  -PORTS:P3.10-TXD0-E*
70  -PORTS:P3.11-RXD0-E*
71  -CLOCK-JTAG-OCDSI:TCK  in
72  -CLOCK-JTAG-OCDSI:TDI  in
73  -CLOCK-JTAG-OCDSI:TDO  out
74  -CLOCK-JTAG-OCDSI:TMS-E*  in
75  -BUS-INTERFACE:P3.12-/BHE-/WRH
76  -PORTS:P3.13-SCLK0-E*
77  -CLOCK-JTAG-OCDSI:P3.15-CLKOUT-F
78  -POWER:VDDI  pwr
79  -POWER:VSSI  pwr
80  -BUS-INTERFACE:P4.0-A16
81  -BUS-INTERFACE:P4.1-A17
82  -BUS-INTERFACE:P4.2-A18
83  -BUS-INTERFACE:P4.3-A19
84  -BUS-INTERFACE:P4.4-A20-C*
85  -BUS-INTERFACE:P4.5-A21-C*
86  -BUS-INTERFACE:P4.6-A22-C*
87  -BUS-INTERFACE:P4.7-A23-C*
88  -POWER:VDDP  pwr
89  -POWER:VSSP  pwr
90  -BUS-INTERFACE:P20.0-/RD
91  -BUS-INTERFACE:P20.1-/WR-/WRL
92  -BUS-INTERFACE:P20.2-READY
93  -BUS-INTERFACE:P20.4-ALE
94  -BUS-INTERFACE:P20.5-/EA
95  -BUS-INTERFACE:P0L.0-AD0
96  -BUS-INTERFACE:P0L.1-AD1
97  -BUS-INTERFACE:P0L.2-AD2
98  -BUS-INTERFACE:P0L.3-AD3
99  -BUS-INTERFACE:P0L.4-AD4
100  -BUS-INTERFACE:P0L.5-AD5
101  -BUS-INTERFACE:P0L.6-AD6
102  -BUS-INTERFACE:P0L.7-AD7
103  -POWER:VDDP  pwr
104  -POWER:VSSP  pwr
105  -BUS-INTERFACE:P0H.0-AD8
106  -BUS-INTERFACE:P0H.1-AD9
111  -BUS-INTERFACE:P0H.2-AD10
112  -BUS-INTERFACE:P0H.3-AD11
113  -BUS-INTERFACE:P0H.4-AD12
114  -BUS-INTERFACE:P0H.5-AD13
115  -BUS-INTERFACE:P0H.6-AD14
116  -BUS-INTERFACE:P0H.7-AD15
117  -BUS-INTERFACE:P1L.0-A0-CC60
118  -BUS-INTERFACE:P1L.1-A1-COUT60
119  -BUS-INTERFACE:P1L.2-A2-CC61
120  -BUS-INTERFACE:P1L.3-A3-COUT61
121  -BUS-INTERFACE:P1L.4-A4-CC62
122  -BUS-INTERFACE:P1L.5-A5-COUT62
123  -BUS-INTERFACE:P1L.6-A6-COUT63
124  -BUS-INTERFACE:P1L.7-A7-/CTRAP-CC22
125  -POWER:VDDP  pwr
126  -POWER:VSSP  pwr
127  -BUS-INTERFACE:P1H.0-A8-/C6P0-CC23-E*
128  -BUS-INTERFACE:P1H.1-A9-/C6P1-MRST1
129  -BUS-INTERFACE:P1H.2-A10-/C6P2-MTSR1
130  -BUS-INTERFACE:P1H.3-A11-SCLK1-E*
131  -BUS-INTERFACE:P1H.4-A12-CC24IO
132  -BUS-INTERFACE:P1H.5-A13-CC25IO
133  -BUS-INTERFACE:P1H.6-A14-CC26IO
134  -BUS-INTERFACE:P1H.7-A15-CC27IO
135  -POWER:VDDI  pwr
136  -POWER:VSSI  pwr
137  -CLOCK-JTAG-OCDSI:XTAL2  out
138  -CLOCK-JTAG-OCDSI:XTAL1  in
139  -POWER:VSSI  pwr
140  -CLOCK-JTAG-OCDSI:XTAL3  in
141  -CLOCK-JTAG-OCDSI:XTAL4  out
142  -BUS-INTERFACE:/RSTIN  in
143  -CLOCK-JTAG-OCDSI:/BRKOUT  out
144  -CLOCK-JTAG-OCDSI:/BRKIN  in

## Footprint P-TQFP-144-19 (pad centres in mm)
P-TQFP-144-19 </b Plastic Metric Quad Flat Package Source: http://www.infineon.com/cgi/ecrm.dll/ecrm/scripts/pack_ov.jsp?oid=23155&cat_oid=-8823
smd 1.35 x 0.29: 1 -10.725,8.75; 2 -10.725,8.25; 3 -10.725,7.75; 4 -10.725,7.25; 5 -10.725,6.75; 6 -10.725,6.25; 7 -10.725,5.75; 8 -10.725,5.25; 9 -10.725,4.75; 10 -10.725,4.25; 11 -10.725,3.75; 12 -10.725,3.25; 13 -10.725,2.75; 14 -10.725,2.25; 15 -10.725,1.75; 16 -10.725,1.25; 17 -10.725,0.75; 18 -10.725,0.25; 19 -10.725,-0.25; 20 -10.725,-0.75; 21 -10.725,-1.25; 22 -10.725,-1.75; 23 -10.725,-2.25; 24 -10.725,-2.75; 25 -10.725,-3.25; 26 -10.725,-3.75; 27 -10.725,-4.25; 28 -10.725,-4.75; 29 -10.725,-5.25; 30 -10.725,-5.75; 31 -10.725,-6.25; 32 -10.725,-6.75; 33 -10.725,-7.25; 34 -10.725,-7.75; 35 -10.725,-8.25; 36 -10.725,-8.75; 73 10.725,-8.75; 74 10.725,-8.25; 75 10.725,-7.75; 76 10.725,-7.25; 77 10.725,-6.75; 78 10.725,-6.25; 79 10.725,-5.75; 80 10.725,-5.25; 81 10.725,-4.75; 82 10.725,-4.25; 83 10.725,-3.75; 84 10.725,-3.25; 85 10.725,-2.75; 86 10.725,-2.25; 87 10.725,-1.75; 88 10.725,-1.25; 89 10.725,-0.75; 90 10.725,-0.25; 91 10.725,0.25; 92 10.725,0.75; 93 10.725,1.25; 94 10.725,1.75; 95 10.725,2.25; 96 10.725,2.75; 97 10.725,3.25; 98 10.725,3.75; 99 10.725,4.25; 100 10.725,4.75; 101 10.725,5.25; 102 10.725,5.75; 103 10.725,6.25; 104 10.725,6.75; 105 10.725,7.25; 106 10.725,7.75; 107 10.725,8.25; 108 10.725,8.75
smd 0.29 x 1.35: 37 -8.75,-10.725; 38 -8.25,-10.725; 39 -7.75,-10.725; 40 -7.25,-10.725; 41 -6.75,-10.725; 42 -6.25,-10.725; 43 -5.75,-10.725; 44 -5.25,-10.725; 45 -4.75,-10.725; 46 -4.25,-10.725; 47 -3.75,-10.725; 48 -3.25,-10.725; 49 -2.75,-10.725; 50 -2.25,-10.725; 51 -1.75,-10.725; 52 -1.25,-10.725; 53 -0.75,-10.725; 54 -0.25,-10.725; 55 0.25,-10.725; 56 0.75,-10.725; 57 1.25,-10.725; 58 1.75,-10.725; 59 2.25,-10.725; 60 2.75,-10.725; 61 3.25,-10.725; 62 3.75,-10.725; 63 4.25,-10.725; 64 4.75,-10.725; 65 5.25,-10.725; 66 5.75,-10.725; 67 6.25,-10.725; 68 6.75,-10.725; 69 7.25,-10.725; 70 7.75,-10.725; 71 8.25,-10.725; 72 8.75,-10.725; 109 8.75,10.725; 110 8.25,10.725; 111 7.75,10.725; 112 7.25,10.725; 113 6.75,10.725; 114 6.25,10.725; 115 5.75,10.725; 116 5.25,10.725; 117 4.75,10.725; 118 4.25,10.725; 119 3.75,10.725; 120 3.25,10.725; 121 2.75,10.725; 122 2.25,10.725; 123 1.75,10.725; 124 1.25,10.725; 125 0.75,10.725; 126 0.25,10.725; 127 -0.25,10.725; 128 -0.75,10.725; 129 -1.25,10.725; 130 -1.75,10.725; 131 -2.25,10.725; 132 -2.75,10.725; 133 -3.25,10.725; 134 -3.75,10.725; 135 -4.25,10.725; 136 -4.75,10.725; 137 -5.25,10.725; 138 -5.75,10.725; 139 -6.25,10.725; 140 -6.75,10.725; 141 -7.25,10.725; 142 -7.75,10.725; 143 -8.25,10.725; 144 -8.75,10.725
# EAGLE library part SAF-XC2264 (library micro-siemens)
16 Bit Microcontroller

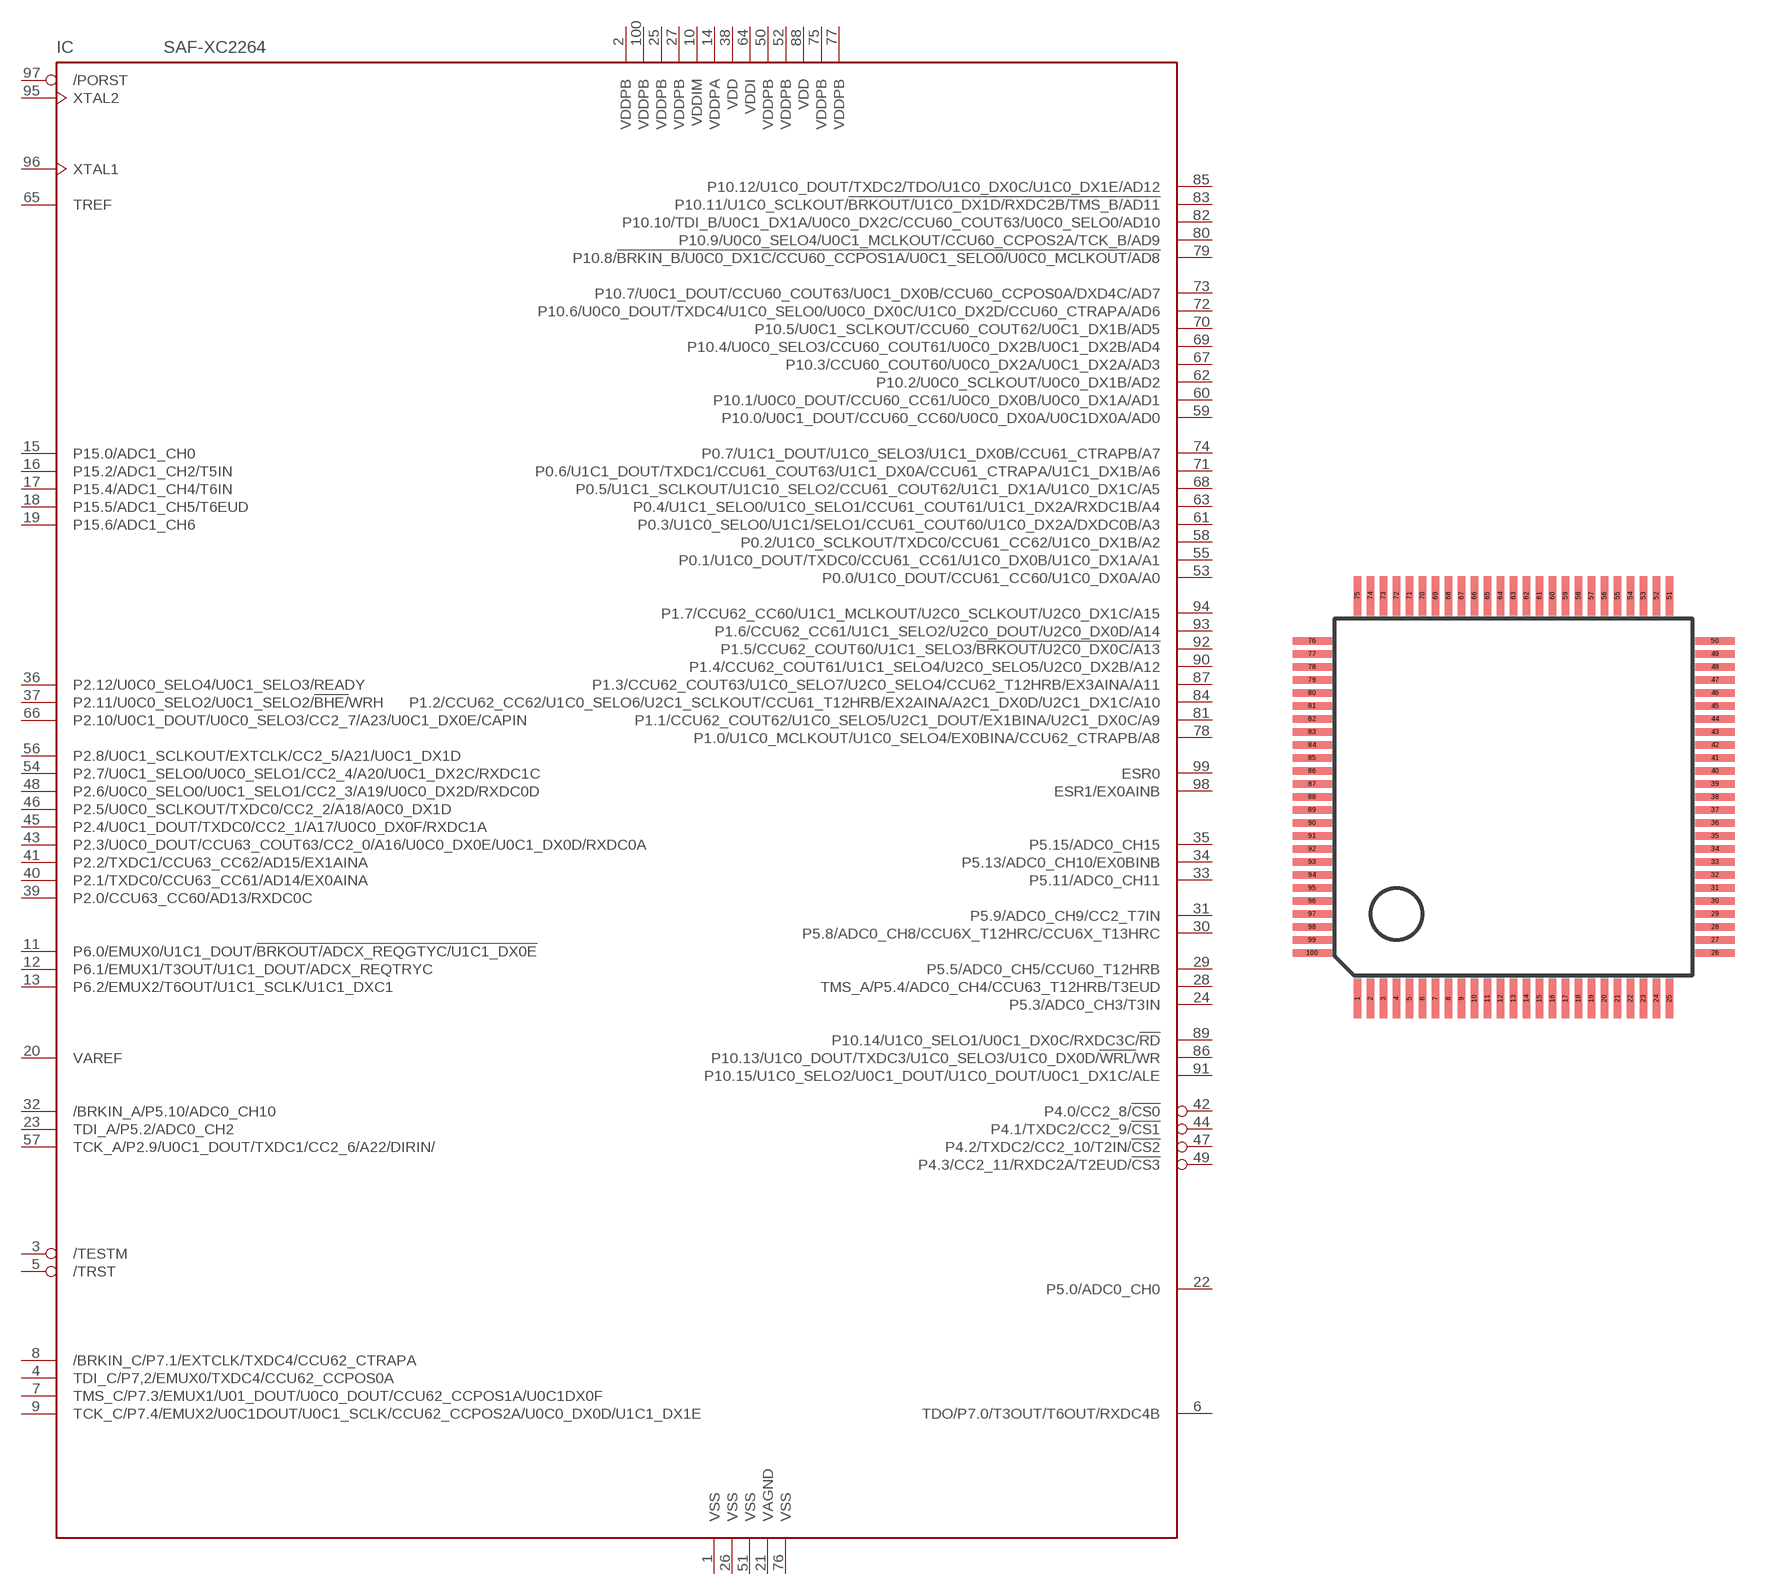
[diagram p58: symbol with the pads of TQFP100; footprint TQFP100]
Designator prefix IC

## SAF-XC2264 (OC_FARNELL: unknown; OC_NEWARK: unknown)  [TQFP100]
1  VSS  pwr
2  VDDPB  pwr
3  /TESTM
4  TDI_C/P7,2/EMUX0/TXDC4/CCU62_CCPOS0A
5  /TRST
6  TDO/P7.0/T3OUT/T6OUT/RXDC4B
7  TMS_C/P7.3/EMUX1/U01_DOUT/U0C0_DOUT/CCU62_CCPOS1A/U0C1DX0F
8  /BRKIN_C/P7.1/EXTCLK/TXDC4/CCU62_CTRAPA
9  TCK_C/P7.4/EMUX2/U0C1DOUT/U0C1_SCLK/CCU62_CCPOS2A/U0C0_DX0D/U1C1_DX1E
10  VDDIM
11  P6.0/EMUX0/U1C1_DOUT/!BRKOUT/ADCX_REQGTYC/U1C1_DX0E
12  P6.1/EMUX1/T3OUT/U1C1_DOUT/ADCX_REQTRYC
13  P6.2/EMUX2/T6OUT/U1C1_SCLK/U1C1_DXC1
14  VDDPA
15  P15.0/ADC1_CH0
16  P15.2/ADC1_CH2/T5IN
17  P15.4/ADC1_CH4/T6IN
18  P15.5/ADC1_CH5/T6EUD
19  P15.6/ADC1_CH6
20  VAREF
21  VAGND
22  P5.0/ADC0_CH0
23  TDI_A/P5.2/ADC0_CH2
24  P5.3/ADC0_CH3/T3IN
25  VDDPB
26  VSS
27  VDDPB
28  TMS_A/P5.4/ADC0_CH4/CCU63_T12HRB/T3EUD
29  P5.5/ADC0_CH5/CCU60_T12HRB
30  P5.8/ADC0_CH8/CCU6X_T12HRC/CCU6X_T13HRC
31  P5.9/ADC0_CH9/CC2_T7IN
32  /BRKIN_A/P5.10/ADC0_CH10
33  P5.11/ADC0_CH11
34  P5.13/ADC0_CH10/EX0BINB
35  P5.15/ADC0_CH15
36  P2.12/U0C0_SELO4/U0C1_SELO3/READY
37  P2.11/U0C0_SELO2/U0C1_SELO2/!BHE/!WRH
38  VDD
39  P2.0/CCU63_CC60/AD13/RXDC0C
40  P2.1/TXDC0/CCU63_CC61/AD14/EX0AINA
41  P2.2/TXDC1/CCU63_CC62/AD15/EX1AINA
42  P4.0/CC2_8/!CS0
43  P2.3/U0C0_DOUT/CCU63_COUT63/CC2_0/A16/U0C0_DX0E/U0C1_DX0D/RXDC0A
44  P4.1/TXDC2/CC2_9/!CS1
45  P2.4/U0C1_DOUT/TXDC0/CC2_1/A17/U0C0_DX0F/RXDC1A
46  P2.5/U0C0_SCLKOUT/TXDC0/CC2_2/A18/A0C0_DX1D
47  P4.2/TXDC2/CC2_10/T2IN/!CS2
48  P2.6/U0C0_SELO0/U0C1_SELO1/CC2_3/A19/U0C0_DX2D/RXDC0D
49  P4.3/CC2_11/RXDC2A/T2EUD/!CS3
50  VDDPB
51  VSS
52  VDDPB
53  P0.0/U1C0_DOUT/CCU61_CC60/U1C0_DX0A/A0
54  P2.7/U0C1_SELO0/U0C0_SELO1/CC2_4/A20/U0C1_DX2C/RXDC1C
55  P0.1/U1C0_DOUT/TXDC0/CCU61_CC61/U1C0_DX0B/U1C0_DX1A/A1
56  P2.8/U0C1_SCLKOUT/EXTCLK/CC2_5/A21/U0C1_DX1D
57  TCK_A/P2.9/U0C1_DOUT/TXDC1/CC2_6/A22/DIRIN/
58  P0.2/U1C0_SCLKOUT/TXDC0/CCU61_CC62/U1C0_DX1B/A2
59  P10.0/U0C1_DOUT/CCU60_CC60/U0C0_DX0A/U0C1DX0A/AD0
60  P10.1/U0C0_DOUT/CCU60_CC61/U0C0_DX0B/U0C0_DX1A/AD1
61  P0.3/U1C0_SELO0/U1C1/SELO1/CCU61_COUT60/U1C0_DX2A/DXDC0B/A3
62  P10.2/U0C0_SCLKOUT/U0C0_DX1B/AD2
63  P0.4/U1C1_SELO0/U1C0_SELO1/CCU61_COUT61/U1C1_DX2A/RXDC1B/A4
64  VDDI
65  TREF
66  P2.10/U0C1_DOUT/U0C0_SELO3/CC2_7/A23/U0C1_DX0E/CAPIN
67  P10.3/CCU60_COUT60/U0C0_DX2A/U0C1_DX2A/AD3
68  P0.5/U1C1_SCLKOUT/U1C10_SELO2/CCU61_COUT62/U1C1_DX1A/U1C0_DX1C/A5
69  P10.4/U0C0_SELO3/CCU60_COUT61/U0C0_DX2B/U0C1_DX2B/AD4
70  P10.5/U0C1_SCLKOUT/CCU60_COUT62/U0C1_DX1B/AD5
71  P0.6/U1C1_DOUT/TXDC1/CCU61_COUT63/U1C1_DX0A/CCU61_CTRAPA/U1C1_DX1B/A6
72  P10.6/U0C0_DOUT/TXDC4/U1C0_SELO0/U0C0_DX0C/U1C0_DX2D/CCU60_CTRAPA/AD6
73  P10.7/U0C1_DOUT/CCU60_COUT63/U0C1_DX0B/CCU60_CCPOS0A/DXD4C/AD7
74  P0.7/U1C1_DOUT/U1C0_SELO3/U1C1_DX0B/CCU61_CTRAPB/A7
75  VDDPB
76  VSS
77  VDDPB
78  P1.0/U1C0_MCLKOUT/U1C0_SELO4/EX0BINA/CCU62_CTRAPB/A8
79  P10.8/!BRKIN_B/U0C0_DX1C/CCU60_CCPOS1A/U0C1_SELO0/U0C0_MCLKOUT/AD8
80  P10.9/U0C0_SELO4/U0C1_MCLKOUT/CCU60_CCPOS2A/TCK_B/AD9
81  P1.1/CCU62_COUT62/U1C0_SELO5/U2C1_DOUT/EX1BINA/U2C1_DX0C/A9
82  P10.10/TDI_B/U0C1_DX1A/U0C0_DX2C/CCU60_COUT63/U0C0_SELO0/AD10
83  P10.11/U1C0_SCLKOUT/!BRKOUT/U1C0_DX1D/RXDC2B/TMS_B/AD11
84  P1.2/CCU62_CC62/U1C0_SELO6/U2C1_SCLKOUT/CCU61_T12HRB/EX2AINA/A2C1_DX0D/U2C1_DX1C/A10
85  P10.12/U1C0_DOUT/TXDC2/TDO/U1C0_DX0C/U1C0_DX1E/AD12
86  P10.13/U1C0_DOUT/TXDC3/U1C0_SELO3/U1C0_DX0D/!WRL/!WR
87  P1.3/CCU62_COUT63/U1C0_SELO7/U2C0_SELO4/CCU62_T12HRB/EX3AINA/A11
88  VDD
89  P10.14/U1C0_SELO1/U0C1_DX0C/RXDC3C/!RD
90  P1.4/CCU62_COUT61/U1C1_SELO4/U2C0_SELO5/U2C0_DX2B/A12
91  P10.15/U1C0_SELO2/U0C1_DOUT/U1C0_DOUT/U0C1_DX1C/ALE
92  P1.5/CCU62_COUT60/U1C1_SELO3/!BRKOUT/U2C0_DX0C/A13
93  P1.6/CCU62_CC61/U1C1_SELO2/U2C0_DOUT/U2C0_DX0D/A14
94  P1.7/CCU62_CC60/U1C1_MCLKOUT/U2C0_SCLKOUT/U2C0_DX1C/A15
95  XTAL2  pwr
96  XTAL1  pwr
97  /PORST
98  ESR1/EX0AINB
99  ESR0
100  VDDPB  pwr

## Footprint TQFP100 (pad centres in mm)
Thin Quad Flat Pack
smd 0.27 x 1.5: 1 -6,-7.75; 2 -5.5,-7.75; 3 -5,-7.75; 4 -4.5,-7.75; 5 -4,-7.75; 6 -3.5,-7.75; 7 -3,-7.75; 8 -2.5,-7.75; 9 -2,-7.75; 10 -1.5,-7.75; 11 -1,-7.75; 12 -0.5,-7.75; 13 0,-7.75; 14 0.5,-7.75; 15 1,-7.75; 16 1.5,-7.75; 17 2,-7.75; 18 2.5,-7.75; 19 3,-7.75; 20 3.5,-7.75; 21 4,-7.75; 22 4.5,-7.75; 23 5,-7.75; 24 5.5,-7.75; 25 6,-7.75; 51 6,7.75; 52 5.5,7.75; 53 5,7.75; 54 4.5,7.75; 55 4,7.75; 56 3.5,7.75; 57 3,7.75; 58 2.5,7.75; 59 2,7.75; 60 1.5,7.75; 61 1,7.75; 62 0.5,7.75; 63 0,7.75; 64 -0.5,7.75; 65 -1,7.75; 66 -1.5,7.75; 67 -2,7.75; 68 -2.5,7.75; 69 -3,7.75; 70 -3.5,7.75; 71 -4,7.75; 72 -4.5,7.75; 73 -5,7.75; 74 -5.5,7.75; 75 -6,7.75
smd 1.5 x 0.27: 26 7.75,-6; 27 7.75,-5.5; 28 7.75,-5; 29 7.75,-4.5; 30 7.75,-4; 31 7.75,-3.5; 32 7.75,-3; 33 7.75,-2.5; 34 7.75,-2; 35 7.75,-1.5; 36 7.75,-1; 37 7.75,-0.5; 38 7.75,0; 39 7.75,0.5; 40 7.75,1; 41 7.75,1.5; 42 7.75,2; 43 7.75,2.5; 44 7.75,3; 45 7.75,3.5; 46 7.75,4; 47 7.75,4.5; 48 7.75,5; 49 7.75,5.5; 50 7.75,6; 76 -7.75,6; 77 -7.75,5.5; 78 -7.75,5; 79 -7.75,4.5; 80 -7.75,4; 81 -7.75,3.5; 82 -7.75,3; 83 -7.75,2.5; 84 -7.75,2; 85 -7.75,1.5; 86 -7.75,1; 87 -7.75,0.5; 88 -7.75,0; 89 -7.75,-0.5; 90 -7.75,-1; 91 -7.75,-1.5; 92 -7.75,-2; 93 -7.75,-2.5; 94 -7.75,-3; 95 -7.75,-3.5; 96 -7.75,-4; 97 -7.75,-4.5; 98 -7.75,-5; 99 -7.75,-5.5; 100 -7.75,-6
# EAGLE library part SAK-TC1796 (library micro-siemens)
TC1796 32-Bit Single Chip Microcontroller

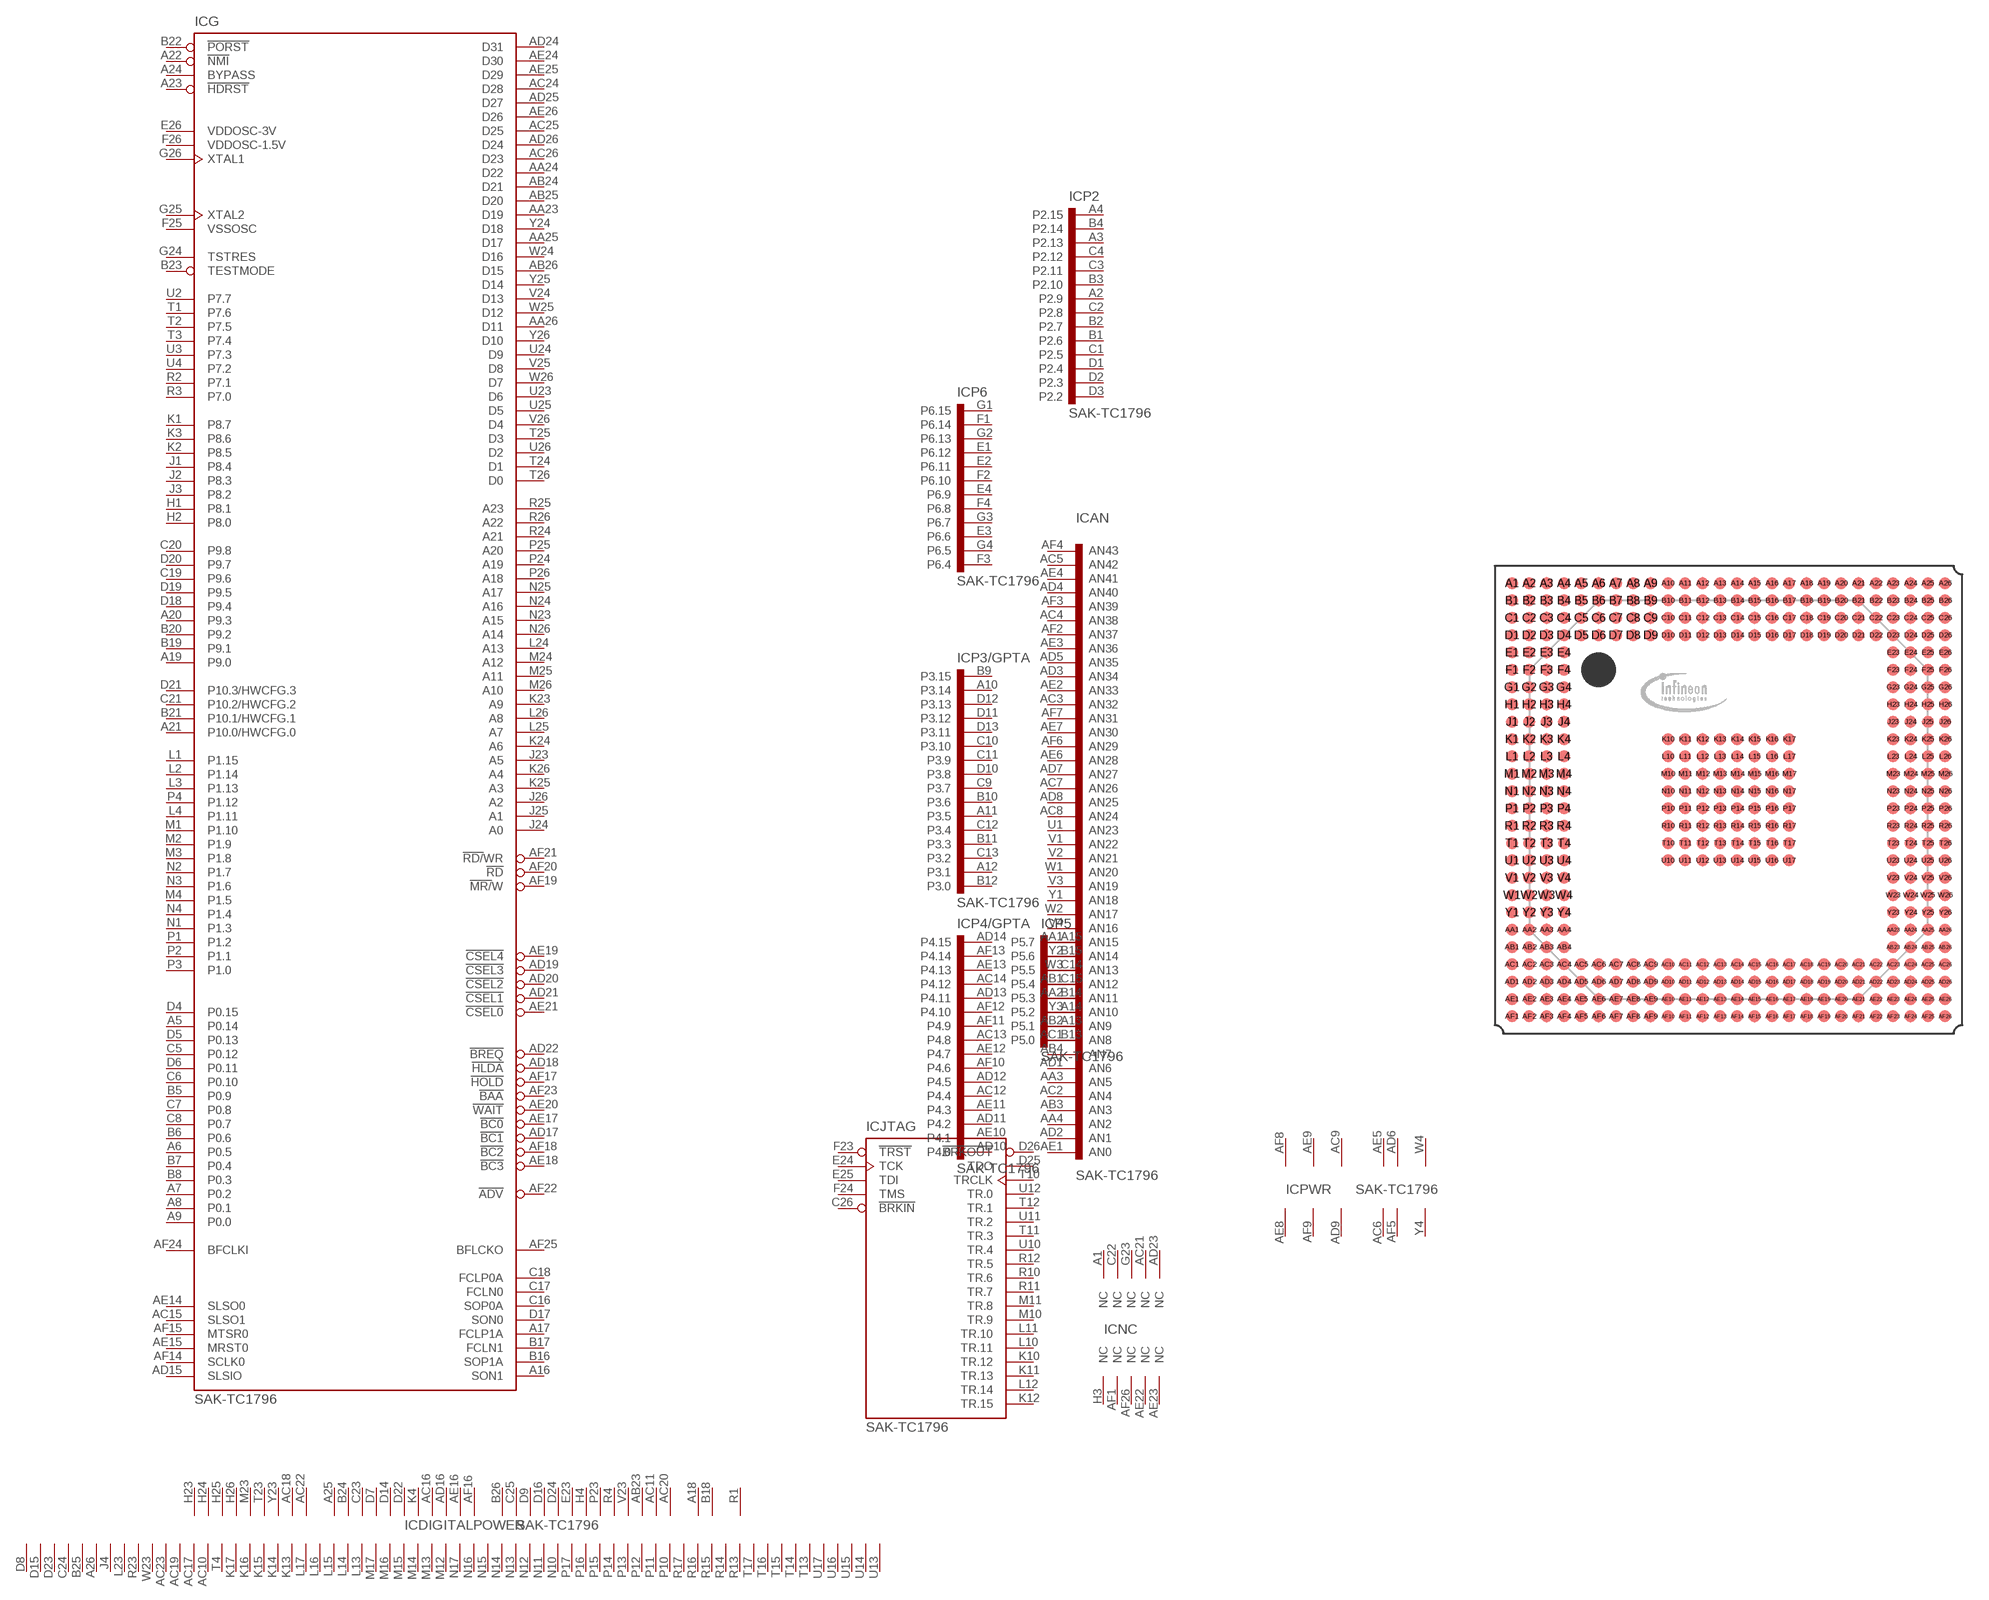
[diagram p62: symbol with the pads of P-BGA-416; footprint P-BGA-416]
Designator prefix IC; gates JTAG=TC1796JTAG P2=TC1796-P2 P3/GPTA=TC1796P3 P4/GPTA=TC1796P4 P5=TC1796P5 P6=TC1796P6 DIGITALPOWER=TC1796PWRD PWR=TC1796PWRA AN=TC1796AN G=TC1796 NC=TC1796NC

## SAK-TC1796 (OC_FARNELL: unknown; OC_NEWARK: unknown)  [P-BGA-416]
A1  NC:NC  nc
A2  P2:P2.9
A3  P2:P2.13
A4  P2:P2.15
A5  G:P0.14
A6  G:P0.5
A7  G:P0.2
A8  G:P0.1
A9  G:P0.0
A10  P3/GPTA:P3.14
A11  P3/GPTA:P3.5
A12  P3/GPTA:P3.1
A13  P5:P5.1
A14  P5:P5.2
A15  P5:P5.7
A16  G:SON1  out
A17  G:FCLP1A  out
A18  DIGITALPOWER:VDDFL3  pwr
A19  G:P9.0
A20  G:P9.3
A21  G:P10.0/HWCFG.0
A22  G:!NMI  in
A23  G:!HDRST
A24  G:BYPASS  in
A25  DIGITALPOWER:VDDP  pwr
A26  DIGITALPOWER:VSS  pwr
AA1  AN:AN15  in
AA2  AN:AN11  in
AA3  AN:AN5  in
AA4  AN:AN2  in
AA23  G:D19  hiz
AA24  G:D22  hiz
AA25  G:D17  hiz
AA26  G:D11  hiz
AB1  AN:AN12  in
AB2  AN:AN9  in
AB3  AN:AN3  in
AB4  AN:AN7  in
AB23  DIGITALPOWER:VDD  pwr
AB24  G:D21  hiz
AB25  G:D20  hiz
AB26  G:D15  hiz
AC1  AN:AN8  in
AC2  AN:AN4  in
AC3  AN:AN32  in
AC4  AN:AN38  in
AC5  AN:AN42  in
AC6  PWR:VAGND  pwr
AC7  AN:AN26  in
AC8  AN:AN24  in
AC9  PWR:VDDAF  pwr
AC10  DIGITALPOWER:VSS  pwr
AC11  DIGITALPOWER:VDD  pwr
AC12  P4/GPTA:P4.4
AC13  P4/GPTA:P4.8
AC14  P4/GPTA:P4.12
AC15  G:SLSO1
AC16  DIGITALPOWER:VDDP  pwr
AC17  DIGITALPOWER:VSS  pwr
AC18  DIGITALPOWER:VDDEBU  pwr
AC19  DIGITALPOWER:VSS  pwr
AC20  DIGITALPOWER:VDD  pwr
AC21  NC:NC  nc
AC22  DIGITALPOWER:VDDEBU  pwr
AC23  DIGITALPOWER:VSS  pwr
AC24  G:D28  hiz
AC25  G:D25  hiz
AC26  G:D23  hiz
AD1  AN:AN6  in
AD2  AN:AN1  in
AD3  AN:AN34  in
AD4  AN:AN40  in
AD5  AN:AN35  in
AD6  PWR:VAREF  pwr
AD7  AN:AN27  in
AD8  AN:AN25  in
AD9  PWR:VSSAF  pwr
AD10  P4/GPTA:P4.0
AD11  P4/GPTA:P4.2
AD12  P4/GPTA:P4.5
AD13  P4/GPTA:P4.11
AD14  P4/GPTA:P4.15
AD15  G:SLSIO
AD16  DIGITALPOWER:VDDP  pwr
AD17  G:!BC1  out
AD18  G:!HLDA  out
AD19  G:!CSEL3  out
AD20  G:!CSEL2  out
AD21  G:!CSEL1  out
AD22  G:!BREQ  out
AD23  NC:NC  nc
AD24  G:D31  hiz
AD25  G:D27  hiz
AD26  G:D24  hiz
AE1  AN:AN0  in
AE2  AN:AN33  in
AE3  AN:AN36  in
AE4  AN:AN41  in
AE5  PWR:VAREF  pwr
AE6  AN:AN28  in
AE7  AN:AN30  in
AE8  PWR:VFAGND  pwr
AE9  PWR:VDDMF  pwr
AE10  P4/GPTA:P4.1
AE11  P4/GPTA:P4.3
AE12  P4/GPTA:P4.7
AE13  P4/GPTA:P4.13
AE14  G:SLSO0
AE15  G:MRST0
AE16  DIGITALPOWER:VDDP  pwr
AE17  G:!BC0  out
AE18  G:!BC3  out
AE19  G:!CSEL4  out
AE20  G:!WAIT  out
AE21  G:!CSEL0  out
AE22  NC:NC  nc
AE23  NC:NC  nc
AE24  G:D30  hiz
AE25  G:D29  hiz
AE26  G:D26  hiz
AF1  NC:NC  nc
AF2  AN:AN37  in
AF3  AN:AN39  in
AF4  AN:AN43  in
AF5  PWR:VAGND  pwr
AF6  AN:AN29  in
AF7  AN:AN31  in
AF8  PWR:VFAREF  pwr
AF9  PWR:VSSMF  pwr
AF10  P4/GPTA:P4.6
AF11  P4/GPTA:P4.9
AF12  P4/GPTA:P4.10
AF13  P4/GPTA:P4.14
AF14  G:SCLK0
AF15  G:MTSR0
AF16  DIGITALPOWER:VDDP  pwr
AF17  G:!HOLD  out
AF18  G:!BC2  out
AF19  G:!MR/!W  out
AF20  G:!RD  out
AF21  G:!RD/!WR  out
AF22  G:!ADV  out
AF23  G:!BAA  out
AF24  G:BFCLKI  in
AF25  G:BFLCKO  out
AF26  NC:NC  nc
B1  P2:P2.6
B2  P2:P2.7
B3  P2:P2.10
B4  P2:P2.14
B5  G:P0.9
B6  G:P0.6
B7  G:P0.4
B8  G:P0.3
B9  P3/GPTA:P3.15
B10  P3/GPTA:P3.6
B11  P3/GPTA:P3.3
B12  P3/GPTA:P3.0
B13  P5:P5.0
B14  P5:P5.3
B15  P5:P5.6
B16  G:SOP1A  out
B17  G:FCLN1  out
B18  DIGITALPOWER:VDDFL3  pwr
B19  G:P9.1
B20  G:P9.2
B21  G:P10.1/HWCFG.1
B22  G:!PORST  in
B23  G:TESTMODE  in
B24  DIGITALPOWER:VDDP  pwr
B25  DIGITALPOWER:VSS  pwr
B26  DIGITALPOWER:VDD  pwr
C1  P2:P2.5
C2  P2:P2.8
C3  P2:P2.11
C4  P2:P2.12
C5  G:P0.12
C6  G:P0.10
C7  G:P0.8
C8  G:P0.7
C9  P3/GPTA:P3.7
C10  P3/GPTA:P3.10
C11  P3/GPTA:P3.9
C12  P3/GPTA:P3.4
C13  P3/GPTA:P3.2
C14  P5:P5.5
C15  P5:P5.4
C16  G:SOP0A  out
C17  G:FCLN0  out
C18  G:FCLP0A  out
C19  G:P9.6
C20  G:P9.8
C21  G:P10.2/HWCFG.2
C22  NC:NC  nc
C23  DIGITALPOWER:VDDP  pwr
C24  DIGITALPOWER:VSS  pwr
C25  DIGITALPOWER:VDD  pwr
C26  JTAG:!BRKIN  in
D1  P2:P2.4
D2  P2:P2.3
D3  P2:P2.2
D4  G:P0.15
D5  G:P0.13
D6  G:P0.11
D7  DIGITALPOWER:VDDP  pwr
D8  DIGITALPOWER:VSS  pwr
D9  DIGITALPOWER:VDD  pwr
D10  P3/GPTA:P3.8
D11  P3/GPTA:P3.12
D12  P3/GPTA:P3.13
D13  P3/GPTA:P3.11
D14  DIGITALPOWER:VDDP  pwr
D15  DIGITALPOWER:VSS  pwr
D16  DIGITALPOWER:VDD  pwr
D17  G:SON0  out
D18  G:P9.4
D19  G:P9.5
D20  G:P9.7
D21  G:P10.3/HWCFG.3
D22  DIGITALPOWER:VDDP  pwr
D23  DIGITALPOWER:VSS  pwr
D24  DIGITALPOWER:VDD  pwr
D25  JTAG:TDO  out
D26  JTAG:!BRKOUT  out
E1  P6:P6.12
E2  P6:P6.11
E3  P6:P6.6
E4  P6:P6.9
E23  DIGITALPOWER:VDD  pwr
E24  JTAG:TCK  in
E25  JTAG:TDI  in
E26  G:VDDOSC-3V  nc
F1  P6:P6.14
F2  P6:P6.10
F3  P6:P6.4
F4  P6:P6.8
F23  JTAG:!TRST  in
F24  JTAG:TMS  in
F25  G:VSSOSC  nc
F26  G:VDDOSC-1.5V  nc
G1  P6:P6.15
G2  P6:P6.13
G3  P6:P6.7
G4  P6:P6.5
G23  NC:NC  nc
G24  G:TSTRES  in
G25  G:XTAL2  in
G26  G:XTAL1  in
H1  G:P8.1
H2  G:P8.0
H3  NC:NC  nc
H4  DIGITALPOWER:VDD  pwr
H23  DIGITALPOWER:VDDEBU  pwr
H24  DIGITALPOWER:VDDEBU  pwr
H25  DIGITALPOWER:VDDEBU  pwr
H26  DIGITALPOWER:VDDEBU  pwr
J1  G:P8.4
J2  G:P8.3
J3  G:P8.2
J4  DIGITALPOWER:VSS  pwr
J23  G:A5  out
J24  G:A0  out
J25  G:A1  out
J26  G:A2  out
K1  G:P8.7
K2  G:P8.5
K3  G:P8.6
K4  DIGITALPOWER:VDDP  pwr
K10  JTAG:TR.12  out
K11  JTAG:TR.13  out
K12  JTAG:TR.15  out
K13  DIGITALPOWER:VSS  pwr
K14  DIGITALPOWER:VSS  pwr
K15  DIGITALPOWER:VSS  pwr
K16  DIGITALPOWER:VSS  pwr
K17  DIGITALPOWER:VSS  pwr
K23  G:A9  out
K24  G:A6  out
K25  G:A3  out
K26  G:A4  out
L1  G:P1.15
L2  G:P1.14
L3  G:P1.13
L4  G:P1.11
L10  JTAG:TR.11  out
L11  JTAG:TR.10  out
L12  JTAG:TR.14  out
L13  DIGITALPOWER:VSS  pwr
L14  DIGITALPOWER:VSS  pwr
L15  DIGITALPOWER:VSS  pwr
L16  DIGITALPOWER:VSS  pwr
L17  DIGITALPOWER:VSS  pwr
L23  DIGITALPOWER:VSS  pwr
L24  G:A13  out
L25  G:A7  out
L26  G:A8  out
M1  G:P1.10
M2  G:P1.9
M3  G:P1.8
M4  G:P1.5
M10  JTAG:TR.9  out
M11  JTAG:TR.8  out
M12  DIGITALPOWER:VSS  pwr
M13  DIGITALPOWER:VSS  pwr
M14  DIGITALPOWER:VSS  pwr
M15  DIGITALPOWER:VSS  pwr
M16  DIGITALPOWER:VSS  pwr
M17  DIGITALPOWER:VSS  pwr
M23  DIGITALPOWER:VDDEBU  pwr
M24  G:A12  out
M25  G:A11  out
M26  G:A10  out
N1  G:P1.3
N2  G:P1.7
N3  G:P1.6
N4  G:P1.4
N10  DIGITALPOWER:VSS  pwr
N11  DIGITALPOWER:VSS  pwr
N12  DIGITALPOWER:VSS  pwr
N13  DIGITALPOWER:VSS  pwr
N14  DIGITALPOWER:VSS  pwr
N15  DIGITALPOWER:VSS  pwr
N16  DIGITALPOWER:VSS  pwr
N17  DIGITALPOWER:VSS  pwr
N23  G:A15  out
N24  G:A16  out
N25  G:A17  out
N26  G:A14  out
P1  G:P1.2
P2  G:P1.1
P3  G:P1.0
P4  G:P1.12
P10  DIGITALPOWER:VSS  pwr
P11  DIGITALPOWER:VSS  pwr
P12  DIGITALPOWER:VSS  pwr
P13  DIGITALPOWER:VSS  pwr
P14  DIGITALPOWER:VSS  pwr
P15  DIGITALPOWER:VSS  pwr
P16  DIGITALPOWER:VSS  pwr
P17  DIGITALPOWER:VSS  pwr
P23  DIGITALPOWER:VDD  pwr
P24  G:A19  out
P25  G:A20  out
P26  G:A18  out
R1  DIGITALPOWER:VDDSBRAM  pwr
R2  G:P7.1
R3  G:P7.0
R4  DIGITALPOWER:VDD  pwr
R10  JTAG:TR.6  out
R11  JTAG:TR.7  out
R12  JTAG:TR.5  out
R13  DIGITALPOWER:VSS  pwr
R14  DIGITALPOWER:VSS  pwr
R15  DIGITALPOWER:VSS  pwr
R16  DIGITALPOWER:VSS  pwr
R17  DIGITALPOWER:VSS  pwr
R23  DIGITALPOWER:VSS  pwr
R24  G:A21  out
R25  G:A23  out
R26  G:A22  out
T1  G:P7.6
T2  G:P7.5
T3  G:P7.4
T4  DIGITALPOWER:VSS  pwr
T10  JTAG:TRCLK  out
T11  JTAG:TR.3  out
T12  JTAG:TR.1  out
T13  DIGITALPOWER:VSS  pwr
T14  DIGITALPOWER:VSS  pwr
T15  DIGITALPOWER:VSS  pwr
T16  DIGITALPOWER:VSS  pwr
T17  DIGITALPOWER:VSS  pwr
T23  DIGITALPOWER:VDDEBU  pwr
T24  G:D1  hiz
T25  G:D3  hiz
T26  G:D0  hiz
U1  AN:AN23  in
U2  G:P7.7
U3  G:P7.3
U4  G:P7.2
U10  JTAG:TR.4  out
U11  JTAG:TR.2  out
U12  JTAG:TR.0  out
U13  DIGITALPOWER:VSS  pwr
U14  DIGITALPOWER:VSS  pwr
U15  DIGITALPOWER:VSS  pwr
U16  DIGITALPOWER:VSS  pwr
U17  DIGITALPOWER:VSS  pwr
U23  G:D6  hiz
U24  G:D9  hiz
U25  G:D5  hiz
U26  G:D2  hiz
V1  AN:AN22  in
V2  AN:AN21  in
V3  AN:AN19  in
V4  AN:AN16  in
V23  DIGITALPOWER:VDD  pwr
V24  G:D13  hiz
V25  G:D8  hiz
V26  G:D4  hiz
W1  AN:AN20  in
W2  AN:AN17  in
W3  AN:AN13  in
W4  PWR:VDDM  pwr
W23  DIGITALPOWER:VSS  pwr
W24  G:D16  hiz
W25  G:D12  hiz
W26  G:D7  hiz
Y1  AN:AN18  in
Y2  AN:AN14  in
Y3  AN:AN10  in
Y4  PWR:VSSM  pwr
Y23  DIGITALPOWER:VDDEBU  pwr
Y24  G:D18  hiz
Y25  G:D14  hiz
Y26  G:D10  hiz

## Footprint P-BGA-416 (pad centres in mm)
P-BGA-416 Plastic Low Profile Pitch Ball Grid Array
smd 0.7 x 0.7: A1 -12.5,12.5; A2 -11.5,12.5; A3 -10.5,12.5; A4 -9.5,12.5; A5 -8.5,12.5; A6 -7.5,12.5; A7 -6.5,12.5; A8 -5.5,12.5; A9 -4.5,12.5; A10 -3.5,12.5; A11 -2.5,12.5; A12 -1.5,12.5; A13 -0.5,12.5; A14 0.5,12.5; A15 1.5,12.5; A16 2.5,12.5; A17 3.5,12.5; A18 4.5,12.5; A19 5.5,12.5; A20 6.5,12.5; A21 7.5,12.5; A22 8.5,12.5; A23 9.5,12.5; A24 10.5,12.5; A25 11.5,12.5; A26 12.5,12.5; AA1 -12.5,-7.5; AA2 -11.5,-7.5; AA3 -10.5,-7.5; AA4 -9.5,-7.5; AA23 9.5,-7.5; AA24 10.5,-7.5; AA25 11.5,-7.5; AA26 12.5,-7.5; AB1 -12.5,-8.5; AB2 -11.5,-8.5; AB3 -10.5,-8.5; AB4 -9.5,-8.5; AB23 9.5,-8.5; AB24 10.5,-8.5; AB25 11.5,-8.5; AB26 12.5,-8.5; AC1 -12.5,-9.5; AC2 -11.5,-9.5; AC3 -10.5,-9.5; AC4 -9.5,-9.5; AC5 -8.5,-9.5; AC6 -7.5,-9.5; AC7 -6.5,-9.5; AC8 -5.5,-9.5; AC9 -4.5,-9.5; AC10 -3.5,-9.5; AC11 -2.5,-9.5; AC12 -1.5,-9.5; AC13 -0.5,-9.5; AC14 0.5,-9.5; AC15 1.5,-9.5; AC16 2.5,-9.5; AC17 3.5,-9.5; AC18 4.5,-9.5; AC19 5.5,-9.5; AC20 6.5,-9.5; AC21 7.5,-9.5; AC22 8.5,-9.5; AC23 9.5,-9.5; AC24 10.5,-9.5; AC25 11.5,-9.5; AC26 12.5,-9.5; AD1 -12.5,-10.5; AD2 -11.5,-10.5; AD3 -10.5,-10.5; AD4 -9.5,-10.5; AD5 -8.5,-10.5; AD6 -7.5,-10.5; AD7 -6.5,-10.5; AD8 -5.5,-10.5; AD9 -4.5,-10.5; AD10 -3.5,-10.5; AD11 -2.5,-10.5; AD12 -1.5,-10.5; AD13 -0.5,-10.5; AD14 0.5,-10.5; AD15 1.5,-10.5; AD16 2.5,-10.5; AD17 3.5,-10.5; AD18 4.5,-10.5; AD19 5.5,-10.5; AD20 6.5,-10.5; AD21 7.5,-10.5; AD22 8.5,-10.5; AD23 9.5,-10.5; AD24 10.5,-10.5; AD25 11.5,-10.5; AD26 12.5,-10.5; AE1 -12.5,-11.5; AE2 -11.5,-11.5; AE3 -10.5,-11.5; AE4 -9.5,-11.5; AE5 -8.5,-11.5; AE6 -7.5,-11.5; AE7 -6.5,-11.5; AE8 -5.5,-11.5; AE9 -4.5,-11.5; AE10 -3.5,-11.5; AE11 -2.5,-11.5; AE12 -1.5,-11.5; AE13 -0.5,-11.5; AE14 0.5,-11.5; AE15 1.5,-11.5; AE16 2.5,-11.5; AE17 3.5,-11.5; AE18 4.5,-11.5; AE19 5.5,-11.5; AE20 6.5,-11.5; AE21 7.5,-11.5; AE22 8.5,-11.5; AE23 9.5,-11.5; AE24 10.5,-11.5; AE25 11.5,-11.5; AE26 12.5,-11.5; AF1 -12.5,-12.5; AF2 -11.5,-12.5; AF3 -10.5,-12.5; AF4 -9.5,-12.5; AF5 -8.5,-12.5; AF6 -7.5,-12.5; AF7 -6.5,-12.5; AF8 -5.5,-12.5; AF9 -4.5,-12.5; AF10 -3.5,-12.5; AF11 -2.5,-12.5; AF12 -1.5,-12.5; AF13 -0.5,-12.5; AF14 0.5,-12.5; AF15 1.5,-12.5; AF16 2.5,-12.5; AF17 3.5,-12.5; AF18 4.5,-12.5; AF19 5.5,-12.5; AF20 6.5,-12.5; AF21 7.5,-12.5; AF22 8.5,-12.5; AF23 9.5,-12.5; AF24 10.5,-12.5; AF25 11.5,-12.5; AF26 12.5,-12.5; B1 -12.5,11.5; B2 -11.5,11.5; B3 -10.5,11.5; B4 -9.5,11.5; B5 -8.5,11.5; B6 -7.5,11.5; B7 -6.5,11.5; B8 -5.5,11.5; B9 -4.5,11.5; B10 -3.5,11.5; B11 -2.5,11.5; B12 -1.5,11.5; B13 -0.5,11.5; B14 0.5,11.5; B15 1.5,11.5; B16 2.5,11.5; B17 3.5,11.5; B18 4.5,11.5; B19 5.5,11.5; B20 6.5,11.5; B21 7.5,11.5; B22 8.5,11.5; B23 9.5,11.5; B24 10.5,11.5; B25 11.5,11.5; B26 12.5,11.5; C1 -12.5,10.5; C2 -11.5,10.5; C3 -10.5,10.5; C4 -9.5,10.5; C5 -8.5,10.5; C6 -7.5,10.5; C7 -6.5,10.5; C8 -5.5,10.5; C9 -4.5,10.5; C10 -3.5,10.5; C11 -2.5,10.5; C12 -1.5,10.5; C13 -0.5,10.5; C14 0.5,10.5; C15 1.5,10.5; C16 2.5,10.5; C17 3.5,10.5; C18 4.5,10.5; C19 5.5,10.5; C20 6.5,10.5; C21 7.5,10.5; C22 8.5,10.5; C23 9.5,10.5; C24 10.5,10.5; C25 11.5,10.5; C26 12.5,10.5; D1 -12.5,9.5; D2 -11.5,9.5; D3 -10.5,9.5; D4 -9.5,9.5; D5 -8.5,9.5; D6 -7.5,9.5; D7 -6.5,9.5; D8 -5.5,9.5; D9 -4.5,9.5; D10 -3.5,9.5; D11 -2.5,9.5; D12 -1.5,9.5; D13 -0.5,9.5; D14 0.5,9.5; D15 1.5,9.5; D16 2.5,9.5; D17 3.5,9.5; D18 4.5,9.5; D19 5.5,9.5; D20 6.5,9.5; D21 7.5,9.5; D22 8.5,9.5; D23 9.5,9.5; D24 10.5,9.5; D25 11.5,9.5; D26 12.5,9.5; E1 -12.5,8.5; E2 -11.5,8.5; E3 -10.5,8.5; E4 -9.5,8.5; E23 9.5,8.5; E24 10.5,8.5; E25 11.5,8.5; E26 12.5,8.5; F1 -12.5,7.5; F2 -11.5,7.5; F3 -10.5,7.5; F4 -9.5,7.5; F23 9.5,7.5; F24 10.5,7.5; F25 11.5,7.5; F26 12.5,7.5; G1 -12.5,6.5; G2 -11.5,6.5; G3 -10.5,6.5; G4 -9.5,6.5; G23 9.5,6.5; G24 10.5,6.5; G25 11.5,6.5; G26 12.5,6.5; H1 -12.5,5.5; H2 -11.5,5.5; H3 -10.5,5.5; H4 -9.5,5.5; H23 9.5,5.5; H24 10.5,5.5; H25 11.5,5.5; H26 12.5,5.5; J1 -12.5,4.5; J2 -11.5,4.5; J3 -10.5,4.5; J4 -9.5,4.5; J23 9.5,4.5; J24 10.5,4.5; J25 11.5,4.5; J26 12.5,4.5; K1 -12.5,3.5; K2 -11.5,3.5; K3 -10.5,3.5; K4 -9.5,3.5; K10 -3.5,3.5; K11 -2.5,3.5; K12 -1.5,3.5; K13 -0.5,3.5; K14 0.5,3.5; K15 1.5,3.5; K16 2.5,3.5; K17 3.5,3.5; K23 9.5,3.5; K24 10.5,3.5; K25 11.5,3.5; K26 12.5,3.5; L1 -12.5,2.5; L2 -11.5,2.5; L3 -10.5,2.5; L4 -9.5,2.5; L10 -3.5,2.5; L11 -2.5,2.5; L12 -1.5,2.5; L13 -0.5,2.5; L14 0.5,2.5; L15 1.5,2.5; L16 2.5,2.5; L17 3.5,2.5; L23 9.5,2.5; L24 10.5,2.5; L25 11.5,2.5; L26 12.5,2.5; M1 -12.5,1.5; M2 -11.5,1.5; M3 -10.5,1.5; M4 -9.5,1.5; M10 -3.5,1.5; M11 -2.5,1.5; M12 -1.5,1.5; M13 -0.5,1.5; M14 0.5,1.5; M15 1.5,1.5; M16 2.5,1.5; M17 3.5,1.5; M23 9.5,1.5; M24 10.5,1.5; M25 11.5,1.5; M26 12.5,1.5; N1 -12.5,0.5; N2 -11.5,0.5; N3 -10.5,0.5; N4 -9.5,0.5; N10 -3.5,0.5; N11 -2.5,0.5; N12 -1.5,0.5; N13 -0.5,0.5; N14 0.5,0.5; N15 1.5,0.5; N16 2.5,0.5; N17 3.5,0.5; N23 9.5,0.5; N24 10.5,0.5; N25 11.5,0.5; N26 12.5,0.5; P1 -12.5,-0.5; P2 -11.5,-0.5; P3 -10.5,-0.5; P4 -9.5,-0.5; P10 -3.5,-0.5; P11 -2.5,-0.5; P12 -1.5,-0.5; P13 -0.5,-0.5; P14 0.5,-0.5; P15 1.5,-0.5; P16 2.5,-0.5; P17 3.5,-0.5; P23 9.5,-0.5; P24 10.5,-0.5; P25 11.5,-0.5; P26 12.5,-0.5; R1 -12.5,-1.5; R2 -11.5,-1.5; R3 -10.5,-1.5; R4 -9.5,-1.5; R10 -3.5,-1.5; R11 -2.5,-1.5; R12 -1.5,-1.5; R13 -0.5,-1.5; R14 0.5,-1.5; R15 1.5,-1.5; R16 2.5,-1.5; R17 3.5,-1.5; R23 9.5,-1.5; R24 10.5,-1.5; R25 11.5,-1.5; R26 12.5,-1.5; T1 -12.5,-2.5; T2 -11.5,-2.5; T3 -10.5,-2.5; T4 -9.5,-2.5; T10 -3.5,-2.5; T11 -2.5,-2.5; T12 -1.5,-2.5; T13 -0.5,-2.5; T14 0.5,-2.5; T15 1.5,-2.5; T16 2.5,-2.5; T17 3.5,-2.5; T23 9.5,-2.5; T24 10.5,-2.5; T25 11.5,-2.5; T26 12.5,-2.5; U1 -12.5,-3.5; U2 -11.5,-3.5; U3 -10.5,-3.5; U4 -9.5,-3.5; U10 -3.5,-3.5; U11 -2.5,-3.5; U12 -1.5,-3.5; U13 -0.5,-3.5; U14 0.5,-3.5; U15 1.5,-3.5; U16 2.5,-3.5; U17 3.5,-3.5; U23 9.5,-3.5; U24 10.5,-3.5; U25 11.5,-3.5; U26 12.5,-3.5; V1 -12.5,-4.5; V2 -11.5,-4.5; V3 -10.5,-4.5; V4 -9.5,-4.5; V23 9.5,-4.5; V24 10.5,-4.5; V25 11.5,-4.5; V26 12.5,-4.5; W1 -12.5,-5.5; W2 -11.5,-5.5; W3 -10.5,-5.5; W4 -9.5,-5.5; W23 9.5,-5.5; W24 10.5,-5.5; W25 11.5,-5.5; W26 12.5,-5.5; Y1 -12.5,-6.5; Y2 -11.5,-6.5; Y3 -10.5,-6.5; Y4 -9.5,-6.5; Y23 9.5,-6.5; Y24 10.5,-6.5; Y25 11.5,-6.5; Y26 12.5,-6.5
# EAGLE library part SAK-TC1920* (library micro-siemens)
32bit Single Chip Microcontroller Source: http://www.infineon.com .. TC1920_umsu_V12.pdf

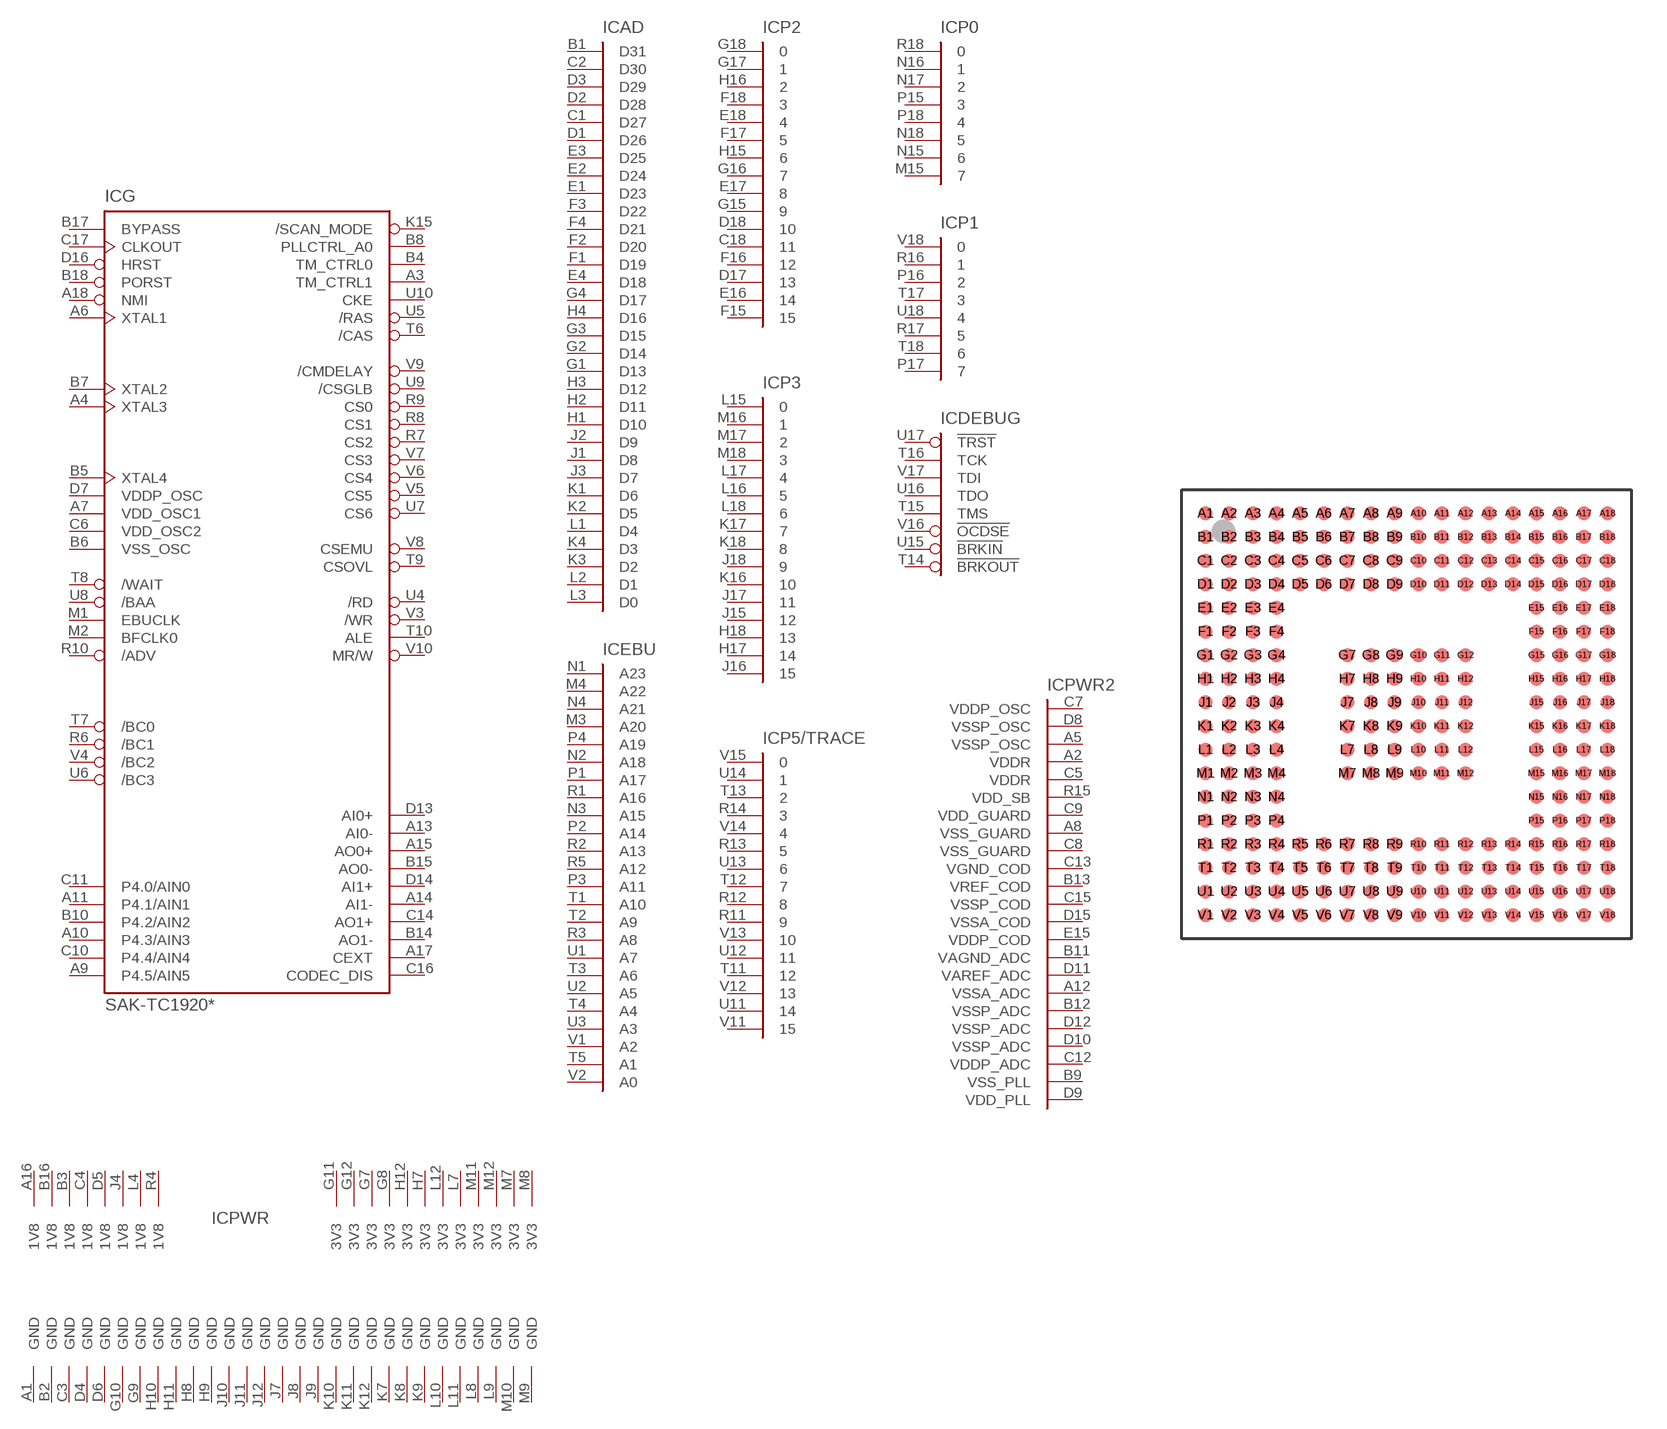
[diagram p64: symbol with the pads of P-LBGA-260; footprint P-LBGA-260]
Designator prefix IC; gates DEBUG=JTAG-OCSD-1 P3=PORT16 P2=PORT16 AD=D31 P1=PORT8 P0=PORT8 EBU=A23 P5/TRACE=PORT16 PWR=TC1920PWR PWR2=TC1920PWR2 G=TC1920

## SAK-TC1920 (OC_FARNELL: unknown; OC_NEWARK: unknown)  [P-LBGA-260]
A1  PWR:GND  pwr
A2  PWR2:VDDR  pwr
A3  G:TM_CTRL1
A4  G:XTAL3
A5  PWR2:VSSP_OSC  pwr
A6  G:XTAL1
A7  G:VDD_OSC1  pwr
A8  PWR2:VSS_GUARD  pwr
A9  G:P4.5/AIN5
A10  G:P4.3/AIN3
A11  G:P4.1/AIN1
A12  PWR2:VSSA_ADC  pwr
A13  G:AI0-
A14  G:AI1-
A15  G:AO0+
A16  PWR:1V8  pwr
A17  G:CEXT
A18  G:NMI  in
B1  AD:D31
B2  PWR:GND  pwr
B3  PWR:1V8  pwr
B4  G:TM_CTRL0
B5  G:XTAL4
B6  G:VSS_OSC  pwr
B7  G:XTAL2
B8  G:PLLCTRL_A0
B9  PWR2:VSS_PLL  pwr
B10  G:P4.2/AIN2
B11  PWR2:VAGND_ADC  pwr
B12  PWR2:VSSP_ADC  pwr
B13  PWR2:VREF_COD  pwr
B14  G:AO1-
B15  G:AO0-
B16  PWR:1V8  pwr
B17  G:BYPASS  in
B18  G:PORST  in
C1  AD:D27
C2  AD:D30
C3  PWR:GND  pwr
C4  PWR:1V8  pwr
C5  PWR2:VDDR  pwr
C6  G:VDD_OSC2  pwr
C7  PWR2:VDDP_OSC  pwr
C8  PWR2:VSS_GUARD  pwr
C9  PWR2:VDD_GUARD  pwr
C10  G:P4.4/AIN4
C11  G:P4.0/AIN0
C12  PWR2:VDDP_ADC  pwr
C13  PWR2:VGND_COD  pwr
C14  G:AO1+
C15  PWR2:VSSP_COD  pwr
C16  G:CODEC_DIS
C17  G:CLKOUT  out
C18  P2:11  in
D1  AD:D26
D2  AD:D28
D3  AD:D29
D4  PWR:GND  pwr
D5  PWR:1V8  pwr
D6  PWR:GND  pwr
D7  G:VDDP_OSC  pwr
D8  PWR2:VSSP_OSC  pwr
D9  PWR2:VDD_PLL  pwr
D10  PWR2:VSSP_ADC  pwr
D11  PWR2:VAREF_ADC  pwr
D12  PWR2:VSSP_ADC  pwr
D13  G:AI0+
D14  G:AI1+
D15  PWR2:VSSA_COD  pwr
D16  G:HRST
D17  P2:13  in
D18  P2:10  in
E1  AD:D23
E2  AD:D24
E3  AD:D25
E4  AD:D18
E15  PWR2:VDDP_COD  pwr
E16  P2:14  in
E17  P2:8  in
E18  P2:4  in
F1  AD:D19
F2  AD:D20
F3  AD:D22
F4  AD:D21
F15  P2:15  in
F16  P2:12  in
F17  P2:5  in
F18  P2:3  in
G1  AD:D13
G2  AD:D14
G3  AD:D15
G4  AD:D17
G7  PWR:3V3  pwr
G8  PWR:3V3  pwr
G9  PWR:GND  pwr
G10  PWR:GND  pwr
G11  PWR:3V3  pwr
G12  PWR:3V3  pwr
G15  P2:9  in
G16  P2:7  in
G17  P2:1  in
G18  P2:0  in
H1  AD:D10
H2  AD:D11
H3  AD:D12
H4  AD:D16
H7  PWR:3V3  pwr
H8  PWR:GND  pwr
H9  PWR:GND  pwr
H10  PWR:GND  pwr
H11  PWR:GND  pwr
H12  PWR:3V3  pwr
H15  P2:6  in
H16  P2:2  in
H17  P3:14  in
H18  P3:13  in
J1  AD:D8
J2  AD:D9
J3  AD:D7
J4  PWR:1V8  pwr
J7  PWR:GND  pwr
J8  PWR:GND  pwr
J9  PWR:GND  pwr
J10  PWR:GND  pwr
J11  PWR:GND  pwr
J12  PWR:GND  pwr
J15  P3:12  in
J16  P3:15  in
J17  P3:11  in
J18  P3:9  in
K1  AD:D6
K2  AD:D5
K3  AD:D2
K4  AD:D3
K7  PWR:GND  pwr
K8  PWR:GND  pwr
K9  PWR:GND  pwr
K10  PWR:GND  pwr
K11  PWR:GND  pwr
K12  PWR:GND  pwr
K15  G:/SCAN_MODE
K16  P3:10  in
K17  P3:7  in
K18  P3:8  in
L1  AD:D4
L2  AD:D1
L3  AD:D0
L4  PWR:1V8  pwr
L7  PWR:3V3  pwr
L8  PWR:GND  pwr
L9  PWR:GND  pwr
L10  PWR:GND  pwr
L11  PWR:GND  pwr
L12  PWR:3V3  pwr
L15  P3:0  in
L16  P3:5  in
L17  P3:4  in
L18  P3:6  in
M1  G:EBUCLK
M2  G:BFCLK0
M3  EBU:A20  out
M4  EBU:A22  out
M7  PWR:3V3  pwr
M8  PWR:3V3  pwr
M9  PWR:GND  pwr
M10  PWR:GND  pwr
M11  PWR:3V3  pwr
M12  PWR:3V3  pwr
M15  P0:7  in
M16  P3:1  in
M17  P3:2  in
M18  P3:3  in
N1  EBU:A23  out
N2  EBU:A18  out
N3  EBU:A15  out
N4  EBU:A21  out
N15  P0:6  in
N16  P0:1  in
N17  P0:2  in
N18  P0:5  in
P1  EBU:A17  out
P2  EBU:A14  out
P3  EBU:A11  out
P4  EBU:A19  out
P15  P0:3  in
P16  P1:2  in
P17  P1:7  in
P18  P0:4  in
R1  EBU:A16  out
R2  EBU:A13  out
R3  EBU:A8  out
R4  PWR:1V8  pwr
R5  EBU:A12  out
R6  G:/BC1
R7  G:CS2
R8  G:CS1
R9  G:CS0
R10  G:/ADV  pwr
R11  P5/TRACE:9  in
R12  P5/TRACE:8  in
R13  P5/TRACE:5  in
R14  P5/TRACE:3  in
R15  PWR2:VDD_SB  pwr
R16  P1:1  in
R17  P1:5  in
R18  P0:0  in
T1  EBU:A10  out
T2  EBU:A9  out
T3  EBU:A6  out
T4  EBU:A4  out
T5  EBU:A1  out
T6  G:/CAS
T7  G:/BC0
T8  G:/WAIT
T9  G:CSOVL
T10  G:ALE
T11  P5/TRACE:12  in
T12  P5/TRACE:7  in
T13  P5/TRACE:2  in
T14  DEBUG:!BRKOUT  out
T15  DEBUG:TMS  in
T16  DEBUG:TCK  in
T17  P1:3  in
T18  P1:6  in
U1  EBU:A7  out
U2  EBU:A5  out
U3  EBU:A3  out
U4  G:/RD
U5  G:/RAS
U6  G:/BC3
U7  G:CS6
U8  G:/BAA
U9  G:/CSGLB
U10  G:CKE
U11  P5/TRACE:14  in
U12  P5/TRACE:11  in
U13  P5/TRACE:6  in
U14  P5/TRACE:1  in
U15  DEBUG:!BRKIN  in
U16  DEBUG:TDO  out
U17  DEBUG:!TRST  in
U18  P1:4  in
V1  EBU:A2  out
V2  EBU:A0  out
V3  G:/WR
V4  G:/BC2
V5  G:CS5
V6  G:CS4
V7  G:CS3
V8  G:CSEMU
V9  G:/CMDELAY
V10  G:MR/W
V11  P5/TRACE:15  in
V12  P5/TRACE:13  in
V13  P5/TRACE:10  in
V14  P5/TRACE:4  in
V15  P5/TRACE:0  in
V16  DEBUG:!OCDSE  in
V17  DEBUG:TDI  in
V18  P1:0  in

## Footprint P-LBGA-260 (pad centres in mm)
P-LBGA-260 Plastic Ball Grid Array Package Source: http://www.infineon.com
smd 0.6 x 0.6: A1 -8.5,8.5; A2 -7.5,8.5; A3 -6.5,8.5; A4 -5.5,8.5; A5 -4.5,8.5; A6 -3.5,8.5; A7 -2.5,8.5; A8 -1.5,8.5; A9 -0.5,8.5; A10 0.5,8.5; A11 1.5,8.5; A12 2.5,8.5; A13 3.5,8.5; A14 4.5,8.5; A15 5.5,8.5; A16 6.5,8.5; A17 7.5,8.5; A18 8.5,8.5; B1 -8.5,7.5; B2 -7.5,7.5; B3 -6.5,7.5; B4 -5.5,7.5; B5 -4.5,7.5; B6 -3.5,7.5; B7 -2.5,7.5; B8 -1.5,7.5; B9 -0.5,7.5; B10 0.5,7.5; B11 1.5,7.5; B12 2.5,7.5; B13 3.5,7.5; B14 4.5,7.5; B15 5.5,7.5; B16 6.5,7.5; B17 7.5,7.5; B18 8.5,7.5; C1 -8.5,6.5; C2 -7.5,6.5; C3 -6.5,6.5; C4 -5.5,6.5; C5 -4.5,6.5; C6 -3.5,6.5; C7 -2.5,6.5; C8 -1.5,6.5; C9 -0.5,6.5; C10 0.5,6.5; C11 1.5,6.5; C12 2.5,6.5; C13 3.5,6.5; C14 4.5,6.5; C15 5.5,6.5; C16 6.5,6.5; C17 7.5,6.5; C18 8.5,6.5; D1 -8.5,5.5; D2 -7.5,5.5; D3 -6.5,5.5; D4 -5.5,5.5; D5 -4.5,5.5; D6 -3.5,5.5; D7 -2.5,5.5; D8 -1.5,5.5; D9 -0.5,5.5; D10 0.5,5.5; D11 1.5,5.5; D12 2.5,5.5; D13 3.5,5.5; D14 4.5,5.5; D15 5.5,5.5; D16 6.5,5.5; D17 7.5,5.5; D18 8.5,5.5; E1 -8.5,4.5; E2 -7.5,4.5; E3 -6.5,4.5; E4 -5.5,4.5; E15 5.5,4.5; E16 6.5,4.5; E17 7.5,4.5; E18 8.5,4.5; F1 -8.5,3.5; F2 -7.5,3.5; F3 -6.5,3.5; F4 -5.5,3.5; F15 5.5,3.5; F16 6.5,3.5; F17 7.5,3.5; F18 8.5,3.5; G1 -8.5,2.5; G2 -7.5,2.5; G3 -6.5,2.5; G4 -5.5,2.5; G7 -2.5,2.5; G8 -1.5,2.5; G9 -0.5,2.5; G10 0.5,2.5; G11 1.5,2.5; G12 2.5,2.5; G15 5.5,2.5; G16 6.5,2.5; G17 7.5,2.5; G18 8.5,2.5; H1 -8.5,1.5; H2 -7.5,1.5; H3 -6.5,1.5; H4 -5.5,1.5; H7 -2.5,1.5; H8 -1.5,1.5; H9 -0.5,1.5; H10 0.5,1.5; H11 1.5,1.5; H12 2.5,1.5; H15 5.5,1.5; H16 6.5,1.5; H17 7.5,1.5; H18 8.5,1.5; J1 -8.5,0.5; J2 -7.5,0.5; J3 -6.5,0.5; J4 -5.5,0.5; J7 -2.5,0.5; J8 -1.5,0.5; J9 -0.5,0.5; J10 0.5,0.5; J11 1.5,0.5; J12 2.5,0.5; J15 5.5,0.5; J16 6.5,0.5; J17 7.5,0.5; J18 8.5,0.5; K1 -8.5,-0.5; K2 -7.5,-0.5; K3 -6.5,-0.5; K4 -5.5,-0.5; K7 -2.5,-0.5; K8 -1.5,-0.5; K9 -0.5,-0.5; K10 0.5,-0.5; K11 1.5,-0.5; K12 2.5,-0.5; K15 5.5,-0.5; K16 6.5,-0.5; K17 7.5,-0.5; K18 8.5,-0.5; L1 -8.5,-1.5; L2 -7.5,-1.5; L3 -6.5,-1.5; L4 -5.5,-1.5; L7 -2.5,-1.5; L8 -1.5,-1.5; L9 -0.5,-1.5; L10 0.5,-1.5; L11 1.5,-1.5; L12 2.5,-1.5; L15 5.5,-1.5; L16 6.5,-1.5; L17 7.5,-1.5; L18 8.5,-1.5; M1 -8.5,-2.5; M2 -7.5,-2.5; M3 -6.5,-2.5; M4 -5.5,-2.5; M7 -2.5,-2.5; M8 -1.5,-2.5; M9 -0.5,-2.5; M10 0.5,-2.5; M11 1.5,-2.5; M12 2.5,-2.5; M15 5.5,-2.5; M16 6.5,-2.5; M17 7.5,-2.5; M18 8.5,-2.5; N1 -8.5,-3.5; N2 -7.5,-3.5; N3 -6.5,-3.5; N4 -5.5,-3.5; N15 5.5,-3.5; N16 6.5,-3.5; N17 7.5,-3.5; N18 8.5,-3.5; P1 -8.5,-4.5; P2 -7.5,-4.5; P3 -6.5,-4.5; P4 -5.5,-4.5; P15 5.5,-4.5; P16 6.5,-4.5; P17 7.5,-4.5; P18 8.5,-4.5; R1 -8.5,-5.5; R2 -7.5,-5.5; R3 -6.5,-5.5; R4 -5.5,-5.5; R5 -4.5,-5.5; R6 -3.5,-5.5; R7 -2.5,-5.5; R8 -1.5,-5.5; R9 -0.5,-5.5; R10 0.5,-5.5; R11 1.5,-5.5; R12 2.5,-5.5; R13 3.5,-5.5; R14 4.5,-5.5; R15 5.5,-5.5; R16 6.5,-5.5; R17 7.5,-5.5; R18 8.5,-5.5; T1 -8.5,-6.5; T2 -7.5,-6.5; T3 -6.5,-6.5; T4 -5.5,-6.5; T5 -4.5,-6.5; T6 -3.5,-6.5; T7 -2.5,-6.5; T8 -1.5,-6.5; T9 -0.5,-6.5; T10 0.5,-6.5; T11 1.5,-6.5; T12 2.5,-6.5; T13 3.5,-6.5; T14 4.5,-6.5; T15 5.5,-6.5; T16 6.5,-6.5; T17 7.5,-6.5; T18 8.5,-6.5; U1 -8.5,-7.5; U2 -7.5,-7.5; U3 -6.5,-7.5; U4 -5.5,-7.5; U5 -4.5,-7.5; U6 -3.5,-7.5; U7 -2.5,-7.5; U8 -1.5,-7.5; U9 -0.5,-7.5; U10 0.5,-7.5; U11 1.5,-7.5; U12 2.5,-7.5; U13 3.5,-7.5; U14 4.5,-7.5; U15 5.5,-7.5; U16 6.5,-7.5; U17 7.5,-7.5; U18 8.5,-7.5; V1 -8.5,-8.5; V2 -7.5,-8.5; V3 -6.5,-8.5; V4 -5.5,-8.5; V5 -4.5,-8.5; V6 -3.5,-8.5; V7 -2.5,-8.5; V8 -1.5,-8.5; V9 -0.5,-8.5; V10 0.5,-8.5; V11 1.5,-8.5; V12 2.5,-8.5; V13 3.5,-8.5; V14 4.5,-8.5; V15 5.5,-8.5; V16 6.5,-8.5; V17 7.5,-8.5; V18 8.5,-8.5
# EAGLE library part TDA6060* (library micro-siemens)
Phase locked loop (PLL) with a multistandard video modulator and a programmable sound FM and AM modulator

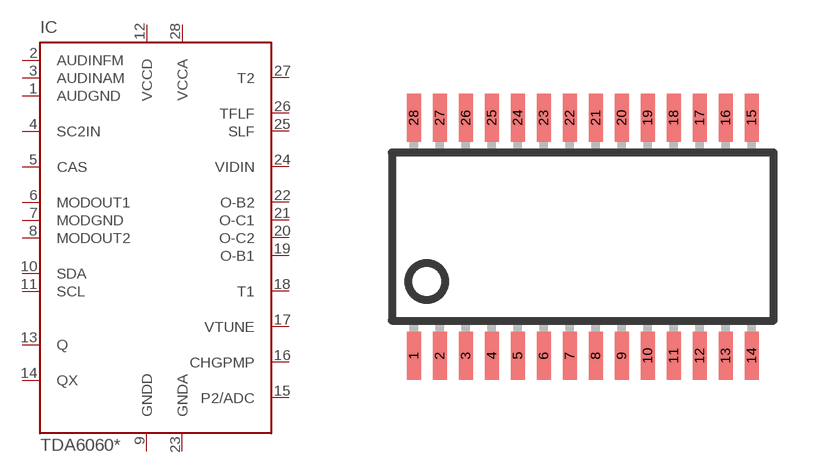
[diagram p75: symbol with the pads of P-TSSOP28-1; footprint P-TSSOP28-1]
Designator prefix IC

## TDA6060G (OC_FARNELL: unknown; OC_NEWARK: unknown), TDA6060XS (OC_FARNELL: unknown; OC_NEWARK: unknown)  [P-TSSOP28-1]
1  AUDGND  pwr
2  AUDINFM  in
3  AUDINAM  in
4  SC2IN  in
5  CAS  in
6  MODOUT1  out
7  MODGND  pwr
8  MODOUT2  out
9  GNDD  pwr
10  SDA  in
11  SCL  in
12  VCCD  pwr
13  Q  pas
14  QX  pas
15  P2/ADC  in
16  CHGPMP  in
17  VTUNE  in
18  T1  in
19  O-B1  in
20  O-C2  pas
21  O-C1  pas
22  O-B2  in
23  GNDA  pwr
24  VIDIN  in
25  SLF  pas
26  TFLF  pas
27  T2  pas
28  VCCA  pwr

## Footprint P-TSSOP28-1 (pad centres in mm)
Infineon P-TSSOP-28-1 TDA 6060 XS cross-ref_pFET-60v_p_chan.pdf
smd 0.35 x 1.2: 1 -4.225,-2.975; 2 -3.575,-2.975; 3 -2.925,-2.975; 4 -2.275,-2.975; 5 -1.625,-2.975; 6 -0.975,-2.975; 7 -0.325,-2.975; 8 0.325,-2.975; 9 0.975,-2.975; 10 1.625,-2.975; 11 2.275,-2.975; 12 2.925,-2.975; 13 3.575,-2.975; 14 4.225,-2.975; 15 4.225,2.975; 16 3.575,2.975; 17 2.925,2.975; 18 2.275,2.975; 19 1.625,2.975; 20 0.975,2.975; 21 0.325,2.975; 22 -0.325,2.975; 23 -0.975,2.975; 24 -1.625,2.975; 25 -2.275,2.975; 26 -2.925,2.975; 27 -3.575,2.975; 28 -4.225,2.975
